VERSION 5.8 ;
BUSBITCHARS "[]" ;
DIVIDERCHAR "/" ;
UNITS
    DATABASE MICRONS 1000 ;
END UNITS

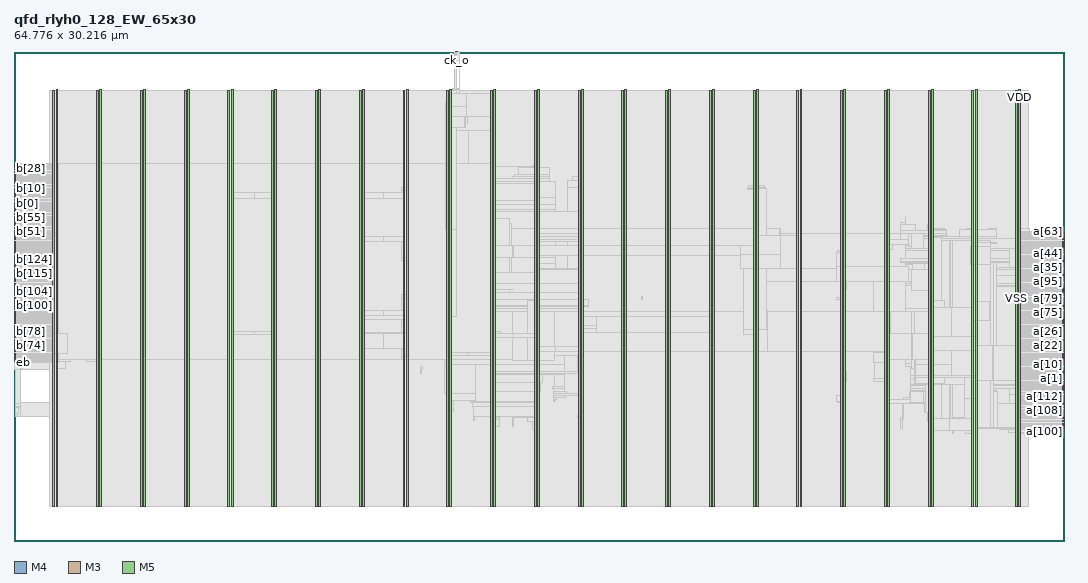
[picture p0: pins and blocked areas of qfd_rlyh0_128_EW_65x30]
MACRO qfd_rlyh0_128_EW_65x30
  FOREIGN qfd_rlyh0_128_EW_65x30 0 0 ;
  CLASS BLOCK ;
  SIZE 64.776 BY 30.216 ;
  PIN a[0]
    DIRECTION INPUT ;
    USE SIGNAL ;
    PORT
      LAYER M4 ;
        RECT  64.692 9.936 64.776 9.96 ;
    END
  END a[0]
  PIN a[100]
    DIRECTION INPUT ;
    USE SIGNAL ;
    PORT
      LAYER M4 ;
        RECT  64.692 7.248 64.776 7.272 ;
    END
  END a[100]
  PIN a[101]
    DIRECTION INPUT ;
    USE SIGNAL ;
    PORT
      LAYER M4 ;
        RECT  64.692 7.344 64.776 7.368 ;
    END
  END a[101]
  PIN a[102]
    DIRECTION INPUT ;
    USE SIGNAL ;
    PORT
      LAYER M4 ;
        RECT  64.692 7.44 64.776 7.464 ;
    END
  END a[102]
  PIN a[103]
    DIRECTION INPUT ;
    USE SIGNAL ;
    PORT
      LAYER M4 ;
        RECT  64.692 7.536 64.776 7.56 ;
    END
  END a[103]
  PIN a[104]
    DIRECTION INPUT ;
    USE SIGNAL ;
    PORT
      LAYER M4 ;
        RECT  64.692 7.632 64.776 7.656 ;
    END
  END a[104]
  PIN a[105]
    DIRECTION INPUT ;
    USE SIGNAL ;
    PORT
      LAYER M4 ;
        RECT  64.692 7.728 64.776 7.752 ;
    END
  END a[105]
  PIN a[106]
    DIRECTION INPUT ;
    USE SIGNAL ;
    PORT
      LAYER M4 ;
        RECT  64.692 7.824 64.776 7.848 ;
    END
  END a[106]
  PIN a[107]
    DIRECTION INPUT ;
    USE SIGNAL ;
    PORT
      LAYER M4 ;
        RECT  64.692 7.92 64.776 7.944 ;
    END
  END a[107]
  PIN a[108]
    DIRECTION INPUT ;
    USE SIGNAL ;
    PORT
      LAYER M4 ;
        RECT  64.692 8.016 64.776 8.04 ;
    END
  END a[108]
  PIN a[109]
    DIRECTION INPUT ;
    USE SIGNAL ;
    PORT
      LAYER M4 ;
        RECT  64.692 8.112 64.776 8.136 ;
    END
  END a[109]
  PIN a[10]
    DIRECTION INPUT ;
    USE SIGNAL ;
    PORT
      LAYER M4 ;
        RECT  64.692 10.896 64.776 10.92 ;
    END
  END a[10]
  PIN a[110]
    DIRECTION INPUT ;
    USE SIGNAL ;
    PORT
      LAYER M4 ;
        RECT  64.692 8.208 64.776 8.232 ;
    END
  END a[110]
  PIN a[111]
    DIRECTION INPUT ;
    USE SIGNAL ;
    PORT
      LAYER M4 ;
        RECT  64.692 8.304 64.776 8.328 ;
    END
  END a[111]
  PIN a[112]
    DIRECTION INPUT ;
    USE SIGNAL ;
    PORT
      LAYER M4 ;
        RECT  64.692 8.4 64.776 8.424 ;
    END
  END a[112]
  PIN a[113]
    DIRECTION INPUT ;
    USE SIGNAL ;
    PORT
      LAYER M4 ;
        RECT  64.692 8.496 64.776 8.52 ;
    END
  END a[113]
  PIN a[114]
    DIRECTION INPUT ;
    USE SIGNAL ;
    PORT
      LAYER M4 ;
        RECT  64.692 8.592 64.776 8.616 ;
    END
  END a[114]
  PIN a[115]
    DIRECTION INPUT ;
    USE SIGNAL ;
    PORT
      LAYER M4 ;
        RECT  64.692 8.688 64.776 8.712 ;
    END
  END a[115]
  PIN a[116]
    DIRECTION INPUT ;
    USE SIGNAL ;
    PORT
      LAYER M4 ;
        RECT  64.692 8.784 64.776 8.808 ;
    END
  END a[116]
  PIN a[117]
    DIRECTION INPUT ;
    USE SIGNAL ;
    PORT
      LAYER M4 ;
        RECT  64.692 8.88 64.776 8.904 ;
    END
  END a[117]
  PIN a[118]
    DIRECTION INPUT ;
    USE SIGNAL ;
    PORT
      LAYER M4 ;
        RECT  64.692 8.976 64.776 9 ;
    END
  END a[118]
  PIN a[119]
    DIRECTION INPUT ;
    USE SIGNAL ;
    PORT
      LAYER M4 ;
        RECT  64.692 9.072 64.776 9.096 ;
    END
  END a[119]
  PIN a[11]
    DIRECTION INPUT ;
    USE SIGNAL ;
    PORT
      LAYER M4 ;
        RECT  64.692 10.992 64.776 11.016 ;
    END
  END a[11]
  PIN a[120]
    DIRECTION INPUT ;
    USE SIGNAL ;
    PORT
      LAYER M4 ;
        RECT  64.692 9.168 64.776 9.192 ;
    END
  END a[120]
  PIN a[121]
    DIRECTION INPUT ;
    USE SIGNAL ;
    PORT
      LAYER M4 ;
        RECT  64.692 9.264 64.776 9.288 ;
    END
  END a[121]
  PIN a[122]
    DIRECTION INPUT ;
    USE SIGNAL ;
    PORT
      LAYER M4 ;
        RECT  64.692 9.36 64.776 9.384 ;
    END
  END a[122]
  PIN a[123]
    DIRECTION INPUT ;
    USE SIGNAL ;
    PORT
      LAYER M4 ;
        RECT  64.692 9.456 64.776 9.48 ;
    END
  END a[123]
  PIN a[124]
    DIRECTION INPUT ;
    USE SIGNAL ;
    PORT
      LAYER M4 ;
        RECT  64.692 9.552 64.776 9.576 ;
    END
  END a[124]
  PIN a[125]
    DIRECTION INPUT ;
    USE SIGNAL ;
    PORT
      LAYER M4 ;
        RECT  64.692 9.648 64.776 9.672 ;
    END
  END a[125]
  PIN a[126]
    DIRECTION INPUT ;
    USE SIGNAL ;
    PORT
      LAYER M4 ;
        RECT  64.692 9.744 64.776 9.768 ;
    END
  END a[126]
  PIN a[127]
    DIRECTION INPUT ;
    USE SIGNAL ;
    PORT
      LAYER M4 ;
        RECT  64.692 9.84 64.776 9.864 ;
    END
  END a[127]
  PIN a[12]
    DIRECTION INPUT ;
    USE SIGNAL ;
    PORT
      LAYER M4 ;
        RECT  64.692 11.088 64.776 11.112 ;
    END
  END a[12]
  PIN a[13]
    DIRECTION INPUT ;
    USE SIGNAL ;
    PORT
      LAYER M4 ;
        RECT  64.692 11.184 64.776 11.208 ;
    END
  END a[13]
  PIN a[14]
    DIRECTION INPUT ;
    USE SIGNAL ;
    PORT
      LAYER M4 ;
        RECT  64.692 11.28 64.776 11.304 ;
    END
  END a[14]
  PIN a[15]
    DIRECTION INPUT ;
    USE SIGNAL ;
    PORT
      LAYER M4 ;
        RECT  64.692 11.376 64.776 11.4 ;
    END
  END a[15]
  PIN a[16]
    DIRECTION INPUT ;
    USE SIGNAL ;
    PORT
      LAYER M4 ;
        RECT  64.692 11.472 64.776 11.496 ;
    END
  END a[16]
  PIN a[17]
    DIRECTION INPUT ;
    USE SIGNAL ;
    PORT
      LAYER M4 ;
        RECT  64.692 11.568 64.776 11.592 ;
    END
  END a[17]
  PIN a[18]
    DIRECTION INPUT ;
    USE SIGNAL ;
    PORT
      LAYER M4 ;
        RECT  64.692 11.664 64.776 11.688 ;
    END
  END a[18]
  PIN a[19]
    DIRECTION INPUT ;
    USE SIGNAL ;
    PORT
      LAYER M4 ;
        RECT  64.692 11.76 64.776 11.784 ;
    END
  END a[19]
  PIN a[1]
    DIRECTION INPUT ;
    USE SIGNAL ;
    PORT
      LAYER M4 ;
        RECT  64.692 10.032 64.776 10.056 ;
    END
  END a[1]
  PIN a[20]
    DIRECTION INPUT ;
    USE SIGNAL ;
    PORT
      LAYER M4 ;
        RECT  64.692 11.856 64.776 11.88 ;
    END
  END a[20]
  PIN a[21]
    DIRECTION INPUT ;
    USE SIGNAL ;
    PORT
      LAYER M4 ;
        RECT  64.692 11.952 64.776 11.976 ;
    END
  END a[21]
  PIN a[22]
    DIRECTION INPUT ;
    USE SIGNAL ;
    PORT
      LAYER M4 ;
        RECT  64.692 12.048 64.776 12.072 ;
    END
  END a[22]
  PIN a[23]
    DIRECTION INPUT ;
    USE SIGNAL ;
    PORT
      LAYER M4 ;
        RECT  64.692 12.144 64.776 12.168 ;
    END
  END a[23]
  PIN a[24]
    DIRECTION INPUT ;
    USE SIGNAL ;
    PORT
      LAYER M4 ;
        RECT  64.692 12.24 64.776 12.264 ;
    END
  END a[24]
  PIN a[25]
    DIRECTION INPUT ;
    USE SIGNAL ;
    PORT
      LAYER M4 ;
        RECT  64.692 12.336 64.776 12.36 ;
    END
  END a[25]
  PIN a[26]
    DIRECTION INPUT ;
    USE SIGNAL ;
    PORT
      LAYER M4 ;
        RECT  64.692 12.432 64.776 12.456 ;
    END
  END a[26]
  PIN a[27]
    DIRECTION INPUT ;
    USE SIGNAL ;
    PORT
      LAYER M4 ;
        RECT  64.692 12.528 64.776 12.552 ;
    END
  END a[27]
  PIN a[28]
    DIRECTION INPUT ;
    USE SIGNAL ;
    PORT
      LAYER M4 ;
        RECT  64.692 12.624 64.776 12.648 ;
    END
  END a[28]
  PIN a[29]
    DIRECTION INPUT ;
    USE SIGNAL ;
    PORT
      LAYER M4 ;
        RECT  64.692 12.72 64.776 12.744 ;
    END
  END a[29]
  PIN a[2]
    DIRECTION INPUT ;
    USE SIGNAL ;
    PORT
      LAYER M4 ;
        RECT  64.692 10.128 64.776 10.152 ;
    END
  END a[2]
  PIN a[30]
    DIRECTION INPUT ;
    USE SIGNAL ;
    PORT
      LAYER M4 ;
        RECT  64.692 12.816 64.776 12.84 ;
    END
  END a[30]
  PIN a[31]
    DIRECTION INPUT ;
    USE SIGNAL ;
    PORT
      LAYER M4 ;
        RECT  64.692 12.912 64.776 12.936 ;
    END
  END a[31]
  PIN a[32]
    DIRECTION INPUT ;
    USE SIGNAL ;
    PORT
      LAYER M4 ;
        RECT  64.692 16.08 64.776 16.104 ;
    END
  END a[32]
  PIN a[33]
    DIRECTION INPUT ;
    USE SIGNAL ;
    PORT
      LAYER M4 ;
        RECT  64.692 16.176 64.776 16.2 ;
    END
  END a[33]
  PIN a[34]
    DIRECTION INPUT ;
    USE SIGNAL ;
    PORT
      LAYER M4 ;
        RECT  64.692 16.272 64.776 16.296 ;
    END
  END a[34]
  PIN a[35]
    DIRECTION INPUT ;
    USE SIGNAL ;
    PORT
      LAYER M4 ;
        RECT  64.692 16.368 64.776 16.392 ;
    END
  END a[35]
  PIN a[36]
    DIRECTION INPUT ;
    USE SIGNAL ;
    PORT
      LAYER M4 ;
        RECT  64.692 16.464 64.776 16.488 ;
    END
  END a[36]
  PIN a[37]
    DIRECTION INPUT ;
    USE SIGNAL ;
    PORT
      LAYER M4 ;
        RECT  64.692 16.56 64.776 16.584 ;
    END
  END a[37]
  PIN a[38]
    DIRECTION INPUT ;
    USE SIGNAL ;
    PORT
      LAYER M4 ;
        RECT  64.692 16.656 64.776 16.68 ;
    END
  END a[38]
  PIN a[39]
    DIRECTION INPUT ;
    USE SIGNAL ;
    PORT
      LAYER M4 ;
        RECT  64.692 16.752 64.776 16.776 ;
    END
  END a[39]
  PIN a[3]
    DIRECTION INPUT ;
    USE SIGNAL ;
    PORT
      LAYER M4 ;
        RECT  64.692 10.224 64.776 10.248 ;
    END
  END a[3]
  PIN a[40]
    DIRECTION INPUT ;
    USE SIGNAL ;
    PORT
      LAYER M4 ;
        RECT  64.692 16.848 64.776 16.872 ;
    END
  END a[40]
  PIN a[41]
    DIRECTION INPUT ;
    USE SIGNAL ;
    PORT
      LAYER M4 ;
        RECT  64.692 16.944 64.776 16.968 ;
    END
  END a[41]
  PIN a[42]
    DIRECTION INPUT ;
    USE SIGNAL ;
    PORT
      LAYER M4 ;
        RECT  64.692 17.04 64.776 17.064 ;
    END
  END a[42]
  PIN a[43]
    DIRECTION INPUT ;
    USE SIGNAL ;
    PORT
      LAYER M4 ;
        RECT  64.692 17.136 64.776 17.16 ;
    END
  END a[43]
  PIN a[44]
    DIRECTION INPUT ;
    USE SIGNAL ;
    PORT
      LAYER M4 ;
        RECT  64.692 17.232 64.776 17.256 ;
    END
  END a[44]
  PIN a[45]
    DIRECTION INPUT ;
    USE SIGNAL ;
    PORT
      LAYER M4 ;
        RECT  64.692 17.328 64.776 17.352 ;
    END
  END a[45]
  PIN a[46]
    DIRECTION INPUT ;
    USE SIGNAL ;
    PORT
      LAYER M4 ;
        RECT  64.692 17.424 64.776 17.448 ;
    END
  END a[46]
  PIN a[47]
    DIRECTION INPUT ;
    USE SIGNAL ;
    PORT
      LAYER M4 ;
        RECT  64.692 17.52 64.776 17.544 ;
    END
  END a[47]
  PIN a[48]
    DIRECTION INPUT ;
    USE SIGNAL ;
    PORT
      LAYER M4 ;
        RECT  64.692 17.616 64.776 17.64 ;
    END
  END a[48]
  PIN a[49]
    DIRECTION INPUT ;
    USE SIGNAL ;
    PORT
      LAYER M4 ;
        RECT  64.692 17.712 64.776 17.736 ;
    END
  END a[49]
  PIN a[4]
    DIRECTION INPUT ;
    USE SIGNAL ;
    PORT
      LAYER M4 ;
        RECT  64.692 10.32 64.776 10.344 ;
    END
  END a[4]
  PIN a[50]
    DIRECTION INPUT ;
    USE SIGNAL ;
    PORT
      LAYER M4 ;
        RECT  64.692 17.808 64.776 17.832 ;
    END
  END a[50]
  PIN a[51]
    DIRECTION INPUT ;
    USE SIGNAL ;
    PORT
      LAYER M4 ;
        RECT  64.692 17.904 64.776 17.928 ;
    END
  END a[51]
  PIN a[52]
    DIRECTION INPUT ;
    USE SIGNAL ;
    PORT
      LAYER M4 ;
        RECT  64.692 18 64.776 18.024 ;
    END
  END a[52]
  PIN a[53]
    DIRECTION INPUT ;
    USE SIGNAL ;
    PORT
      LAYER M4 ;
        RECT  64.692 18.096 64.776 18.12 ;
    END
  END a[53]
  PIN a[54]
    DIRECTION INPUT ;
    USE SIGNAL ;
    PORT
      LAYER M4 ;
        RECT  64.692 18.192 64.776 18.216 ;
    END
  END a[54]
  PIN a[55]
    DIRECTION INPUT ;
    USE SIGNAL ;
    PORT
      LAYER M4 ;
        RECT  64.692 18.288 64.776 18.312 ;
    END
  END a[55]
  PIN a[56]
    DIRECTION INPUT ;
    USE SIGNAL ;
    PORT
      LAYER M4 ;
        RECT  64.692 18.384 64.776 18.408 ;
    END
  END a[56]
  PIN a[57]
    DIRECTION INPUT ;
    USE SIGNAL ;
    PORT
      LAYER M4 ;
        RECT  64.692 18.48 64.776 18.504 ;
    END
  END a[57]
  PIN a[58]
    DIRECTION INPUT ;
    USE SIGNAL ;
    PORT
      LAYER M4 ;
        RECT  64.692 18.576 64.776 18.6 ;
    END
  END a[58]
  PIN a[59]
    DIRECTION INPUT ;
    USE SIGNAL ;
    PORT
      LAYER M4 ;
        RECT  64.692 18.672 64.776 18.696 ;
    END
  END a[59]
  PIN a[5]
    DIRECTION INPUT ;
    USE SIGNAL ;
    PORT
      LAYER M4 ;
        RECT  64.692 10.416 64.776 10.44 ;
    END
  END a[5]
  PIN a[60]
    DIRECTION INPUT ;
    USE SIGNAL ;
    PORT
      LAYER M4 ;
        RECT  64.692 18.768 64.776 18.792 ;
    END
  END a[60]
  PIN a[61]
    DIRECTION INPUT ;
    USE SIGNAL ;
    PORT
      LAYER M4 ;
        RECT  64.692 18.864 64.776 18.888 ;
    END
  END a[61]
  PIN a[62]
    DIRECTION INPUT ;
    USE SIGNAL ;
    PORT
      LAYER M4 ;
        RECT  64.692 18.96 64.776 18.984 ;
    END
  END a[62]
  PIN a[63]
    DIRECTION INPUT ;
    USE SIGNAL ;
    PORT
      LAYER M4 ;
        RECT  64.692 19.056 64.776 19.08 ;
    END
  END a[63]
  PIN a[64]
    DIRECTION INPUT ;
    USE SIGNAL ;
    PORT
      LAYER M4 ;
        RECT  64.692 13.008 64.776 13.032 ;
    END
  END a[64]
  PIN a[65]
    DIRECTION INPUT ;
    USE SIGNAL ;
    PORT
      LAYER M4 ;
        RECT  64.692 13.104 64.776 13.128 ;
    END
  END a[65]
  PIN a[66]
    DIRECTION INPUT ;
    USE SIGNAL ;
    PORT
      LAYER M4 ;
        RECT  64.692 13.2 64.776 13.224 ;
    END
  END a[66]
  PIN a[67]
    DIRECTION INPUT ;
    USE SIGNAL ;
    PORT
      LAYER M4 ;
        RECT  64.692 13.296 64.776 13.32 ;
    END
  END a[67]
  PIN a[68]
    DIRECTION INPUT ;
    USE SIGNAL ;
    PORT
      LAYER M4 ;
        RECT  64.692 13.392 64.776 13.416 ;
    END
  END a[68]
  PIN a[69]
    DIRECTION INPUT ;
    USE SIGNAL ;
    PORT
      LAYER M4 ;
        RECT  64.692 13.488 64.776 13.512 ;
    END
  END a[69]
  PIN a[6]
    DIRECTION INPUT ;
    USE SIGNAL ;
    PORT
      LAYER M4 ;
        RECT  64.692 10.512 64.776 10.536 ;
    END
  END a[6]
  PIN a[70]
    DIRECTION INPUT ;
    USE SIGNAL ;
    PORT
      LAYER M4 ;
        RECT  64.692 13.584 64.776 13.608 ;
    END
  END a[70]
  PIN a[71]
    DIRECTION INPUT ;
    USE SIGNAL ;
    PORT
      LAYER M4 ;
        RECT  64.692 13.68 64.776 13.704 ;
    END
  END a[71]
  PIN a[72]
    DIRECTION INPUT ;
    USE SIGNAL ;
    PORT
      LAYER M4 ;
        RECT  64.692 13.776 64.776 13.8 ;
    END
  END a[72]
  PIN a[73]
    DIRECTION INPUT ;
    USE SIGNAL ;
    PORT
      LAYER M4 ;
        RECT  64.692 13.872 64.776 13.896 ;
    END
  END a[73]
  PIN a[74]
    DIRECTION INPUT ;
    USE SIGNAL ;
    PORT
      LAYER M4 ;
        RECT  64.692 13.968 64.776 13.992 ;
    END
  END a[74]
  PIN a[75]
    DIRECTION INPUT ;
    USE SIGNAL ;
    PORT
      LAYER M4 ;
        RECT  64.692 14.064 64.776 14.088 ;
    END
  END a[75]
  PIN a[76]
    DIRECTION INPUT ;
    USE SIGNAL ;
    PORT
      LAYER M4 ;
        RECT  64.692 14.16 64.776 14.184 ;
    END
  END a[76]
  PIN a[77]
    DIRECTION INPUT ;
    USE SIGNAL ;
    PORT
      LAYER M4 ;
        RECT  64.692 14.256 64.776 14.28 ;
    END
  END a[77]
  PIN a[78]
    DIRECTION INPUT ;
    USE SIGNAL ;
    PORT
      LAYER M4 ;
        RECT  64.692 14.352 64.776 14.376 ;
    END
  END a[78]
  PIN a[79]
    DIRECTION INPUT ;
    USE SIGNAL ;
    PORT
      LAYER M4 ;
        RECT  64.692 14.448 64.776 14.472 ;
    END
  END a[79]
  PIN a[7]
    DIRECTION INPUT ;
    USE SIGNAL ;
    PORT
      LAYER M4 ;
        RECT  64.692 10.608 64.776 10.632 ;
    END
  END a[7]
  PIN a[80]
    DIRECTION INPUT ;
    USE SIGNAL ;
    PORT
      LAYER M4 ;
        RECT  64.692 14.544 64.776 14.568 ;
    END
  END a[80]
  PIN a[81]
    DIRECTION INPUT ;
    USE SIGNAL ;
    PORT
      LAYER M4 ;
        RECT  64.692 14.64 64.776 14.664 ;
    END
  END a[81]
  PIN a[82]
    DIRECTION INPUT ;
    USE SIGNAL ;
    PORT
      LAYER M4 ;
        RECT  64.692 14.736 64.776 14.76 ;
    END
  END a[82]
  PIN a[83]
    DIRECTION INPUT ;
    USE SIGNAL ;
    PORT
      LAYER M4 ;
        RECT  64.692 14.832 64.776 14.856 ;
    END
  END a[83]
  PIN a[84]
    DIRECTION INPUT ;
    USE SIGNAL ;
    PORT
      LAYER M4 ;
        RECT  64.692 14.928 64.776 14.952 ;
    END
  END a[84]
  PIN a[85]
    DIRECTION INPUT ;
    USE SIGNAL ;
    PORT
      LAYER M4 ;
        RECT  64.692 15.024 64.776 15.048 ;
    END
  END a[85]
  PIN a[86]
    DIRECTION INPUT ;
    USE SIGNAL ;
    PORT
      LAYER M4 ;
        RECT  64.692 15.12 64.776 15.144 ;
    END
  END a[86]
  PIN a[87]
    DIRECTION INPUT ;
    USE SIGNAL ;
    PORT
      LAYER M4 ;
        RECT  64.692 15.216 64.776 15.24 ;
    END
  END a[87]
  PIN a[88]
    DIRECTION INPUT ;
    USE SIGNAL ;
    PORT
      LAYER M4 ;
        RECT  64.692 15.312 64.776 15.336 ;
    END
  END a[88]
  PIN a[89]
    DIRECTION INPUT ;
    USE SIGNAL ;
    PORT
      LAYER M4 ;
        RECT  64.692 15.408 64.776 15.432 ;
    END
  END a[89]
  PIN a[8]
    DIRECTION INPUT ;
    USE SIGNAL ;
    PORT
      LAYER M4 ;
        RECT  64.692 10.704 64.776 10.728 ;
    END
  END a[8]
  PIN a[90]
    DIRECTION INPUT ;
    USE SIGNAL ;
    PORT
      LAYER M4 ;
        RECT  64.692 15.504 64.776 15.528 ;
    END
  END a[90]
  PIN a[91]
    DIRECTION INPUT ;
    USE SIGNAL ;
    PORT
      LAYER M4 ;
        RECT  64.692 15.6 64.776 15.624 ;
    END
  END a[91]
  PIN a[92]
    DIRECTION INPUT ;
    USE SIGNAL ;
    PORT
      LAYER M4 ;
        RECT  64.692 15.696 64.776 15.72 ;
    END
  END a[92]
  PIN a[93]
    DIRECTION INPUT ;
    USE SIGNAL ;
    PORT
      LAYER M4 ;
        RECT  64.692 15.792 64.776 15.816 ;
    END
  END a[93]
  PIN a[94]
    DIRECTION INPUT ;
    USE SIGNAL ;
    PORT
      LAYER M4 ;
        RECT  64.692 15.888 64.776 15.912 ;
    END
  END a[94]
  PIN a[95]
    DIRECTION INPUT ;
    USE SIGNAL ;
    PORT
      LAYER M4 ;
        RECT  64.692 15.984 64.776 16.008 ;
    END
  END a[95]
  PIN a[96]
    DIRECTION INPUT ;
    USE SIGNAL ;
    PORT
      LAYER M4 ;
        RECT  64.692 6.864 64.776 6.888 ;
    END
  END a[96]
  PIN a[97]
    DIRECTION INPUT ;
    USE SIGNAL ;
    PORT
      LAYER M4 ;
        RECT  64.692 6.96 64.776 6.984 ;
    END
  END a[97]
  PIN a[98]
    DIRECTION INPUT ;
    USE SIGNAL ;
    PORT
      LAYER M4 ;
        RECT  64.692 7.056 64.776 7.08 ;
    END
  END a[98]
  PIN a[99]
    DIRECTION INPUT ;
    USE SIGNAL ;
    PORT
      LAYER M4 ;
        RECT  64.692 7.152 64.776 7.176 ;
    END
  END a[99]
  PIN a[9]
    DIRECTION INPUT ;
    USE SIGNAL ;
    PORT
      LAYER M4 ;
        RECT  64.692 10.8 64.776 10.824 ;
    END
  END a[9]
  PIN b[0]
    DIRECTION OUTPUT ;
    USE SIGNAL ;
    PORT
      LAYER M4 ;
        RECT  0 20.304 0.084 20.328 ;
    END
  END b[0]
  PIN b[100]
    DIRECTION OUTPUT ;
    USE SIGNAL ;
    PORT
      LAYER M4 ;
        RECT  0 14.544 0.084 14.568 ;
    END
  END b[100]
  PIN b[101]
    DIRECTION OUTPUT ;
    USE SIGNAL ;
    PORT
      LAYER M4 ;
        RECT  0 14.64 0.084 14.664 ;
    END
  END b[101]
  PIN b[102]
    DIRECTION OUTPUT ;
    USE SIGNAL ;
    PORT
      LAYER M4 ;
        RECT  0 14.736 0.084 14.76 ;
    END
  END b[102]
  PIN b[103]
    DIRECTION OUTPUT ;
    USE SIGNAL ;
    PORT
      LAYER M4 ;
        RECT  0 14.832 0.084 14.856 ;
    END
  END b[103]
  PIN b[104]
    DIRECTION OUTPUT ;
    USE SIGNAL ;
    PORT
      LAYER M4 ;
        RECT  0 14.928 0.084 14.952 ;
    END
  END b[104]
  PIN b[105]
    DIRECTION OUTPUT ;
    USE SIGNAL ;
    PORT
      LAYER M4 ;
        RECT  0 15.024 0.084 15.048 ;
    END
  END b[105]
  PIN b[106]
    DIRECTION OUTPUT ;
    USE SIGNAL ;
    PORT
      LAYER M4 ;
        RECT  0 15.12 0.084 15.144 ;
    END
  END b[106]
  PIN b[107]
    DIRECTION OUTPUT ;
    USE SIGNAL ;
    PORT
      LAYER M4 ;
        RECT  0 15.216 0.084 15.24 ;
    END
  END b[107]
  PIN b[108]
    DIRECTION OUTPUT ;
    USE SIGNAL ;
    PORT
      LAYER M4 ;
        RECT  0 15.312 0.084 15.336 ;
    END
  END b[108]
  PIN b[109]
    DIRECTION OUTPUT ;
    USE SIGNAL ;
    PORT
      LAYER M4 ;
        RECT  0 15.408 0.084 15.432 ;
    END
  END b[109]
  PIN b[10]
    DIRECTION OUTPUT ;
    USE SIGNAL ;
    PORT
      LAYER M4 ;
        RECT  0 21.264 0.084 21.288 ;
    END
  END b[10]
  PIN b[110]
    DIRECTION OUTPUT ;
    USE SIGNAL ;
    PORT
      LAYER M4 ;
        RECT  0 15.504 0.084 15.528 ;
    END
  END b[110]
  PIN b[111]
    DIRECTION OUTPUT ;
    USE SIGNAL ;
    PORT
      LAYER M4 ;
        RECT  0 15.6 0.084 15.624 ;
    END
  END b[111]
  PIN b[112]
    DIRECTION OUTPUT ;
    USE SIGNAL ;
    PORT
      LAYER M4 ;
        RECT  0 15.696 0.084 15.72 ;
    END
  END b[112]
  PIN b[113]
    DIRECTION OUTPUT ;
    USE SIGNAL ;
    PORT
      LAYER M4 ;
        RECT  0 15.792 0.084 15.816 ;
    END
  END b[113]
  PIN b[114]
    DIRECTION OUTPUT ;
    USE SIGNAL ;
    PORT
      LAYER M4 ;
        RECT  0 15.888 0.084 15.912 ;
    END
  END b[114]
  PIN b[115]
    DIRECTION OUTPUT ;
    USE SIGNAL ;
    PORT
      LAYER M4 ;
        RECT  0 15.984 0.084 16.008 ;
    END
  END b[115]
  PIN b[116]
    DIRECTION OUTPUT ;
    USE SIGNAL ;
    PORT
      LAYER M4 ;
        RECT  0 16.08 0.084 16.104 ;
    END
  END b[116]
  PIN b[117]
    DIRECTION OUTPUT ;
    USE SIGNAL ;
    PORT
      LAYER M4 ;
        RECT  0 16.176 0.084 16.2 ;
    END
  END b[117]
  PIN b[118]
    DIRECTION OUTPUT ;
    USE SIGNAL ;
    PORT
      LAYER M4 ;
        RECT  0 16.272 0.084 16.296 ;
    END
  END b[118]
  PIN b[119]
    DIRECTION OUTPUT ;
    USE SIGNAL ;
    PORT
      LAYER M4 ;
        RECT  0 16.368 0.084 16.392 ;
    END
  END b[119]
  PIN b[11]
    DIRECTION OUTPUT ;
    USE SIGNAL ;
    PORT
      LAYER M4 ;
        RECT  0 21.36 0.084 21.384 ;
    END
  END b[11]
  PIN b[120]
    DIRECTION OUTPUT ;
    USE SIGNAL ;
    PORT
      LAYER M4 ;
        RECT  0 16.464 0.084 16.488 ;
    END
  END b[120]
  PIN b[121]
    DIRECTION OUTPUT ;
    USE SIGNAL ;
    PORT
      LAYER M4 ;
        RECT  0 16.56 0.084 16.584 ;
    END
  END b[121]
  PIN b[122]
    DIRECTION OUTPUT ;
    USE SIGNAL ;
    PORT
      LAYER M4 ;
        RECT  0 16.656 0.084 16.68 ;
    END
  END b[122]
  PIN b[123]
    DIRECTION OUTPUT ;
    USE SIGNAL ;
    PORT
      LAYER M4 ;
        RECT  0 16.752 0.084 16.776 ;
    END
  END b[123]
  PIN b[124]
    DIRECTION OUTPUT ;
    USE SIGNAL ;
    PORT
      LAYER M4 ;
        RECT  0 16.848 0.084 16.872 ;
    END
  END b[124]
  PIN b[125]
    DIRECTION OUTPUT ;
    USE SIGNAL ;
    PORT
      LAYER M4 ;
        RECT  0 16.944 0.084 16.968 ;
    END
  END b[125]
  PIN b[126]
    DIRECTION OUTPUT ;
    USE SIGNAL ;
    PORT
      LAYER M4 ;
        RECT  0 17.04 0.084 17.064 ;
    END
  END b[126]
  PIN b[127]
    DIRECTION OUTPUT ;
    USE SIGNAL ;
    PORT
      LAYER M4 ;
        RECT  0 17.136 0.084 17.16 ;
    END
  END b[127]
  PIN b[12]
    DIRECTION OUTPUT ;
    USE SIGNAL ;
    PORT
      LAYER M4 ;
        RECT  0 21.456 0.084 21.48 ;
    END
  END b[12]
  PIN b[13]
    DIRECTION OUTPUT ;
    USE SIGNAL ;
    PORT
      LAYER M4 ;
        RECT  0 21.552 0.084 21.576 ;
    END
  END b[13]
  PIN b[14]
    DIRECTION OUTPUT ;
    USE SIGNAL ;
    PORT
      LAYER M4 ;
        RECT  0 21.648 0.084 21.672 ;
    END
  END b[14]
  PIN b[15]
    DIRECTION OUTPUT ;
    USE SIGNAL ;
    PORT
      LAYER M4 ;
        RECT  0 21.744 0.084 21.768 ;
    END
  END b[15]
  PIN b[16]
    DIRECTION OUTPUT ;
    USE SIGNAL ;
    PORT
      LAYER M4 ;
        RECT  0 21.84 0.084 21.864 ;
    END
  END b[16]
  PIN b[17]
    DIRECTION OUTPUT ;
    USE SIGNAL ;
    PORT
      LAYER M4 ;
        RECT  0 21.936 0.084 21.96 ;
    END
  END b[17]
  PIN b[18]
    DIRECTION OUTPUT ;
    USE SIGNAL ;
    PORT
      LAYER M4 ;
        RECT  0 22.032 0.084 22.056 ;
    END
  END b[18]
  PIN b[19]
    DIRECTION OUTPUT ;
    USE SIGNAL ;
    PORT
      LAYER M4 ;
        RECT  0 22.128 0.084 22.152 ;
    END
  END b[19]
  PIN b[1]
    DIRECTION OUTPUT ;
    USE SIGNAL ;
    PORT
      LAYER M4 ;
        RECT  0 20.4 0.084 20.424 ;
    END
  END b[1]
  PIN b[20]
    DIRECTION OUTPUT ;
    USE SIGNAL ;
    PORT
      LAYER M4 ;
        RECT  0 22.224 0.084 22.248 ;
    END
  END b[20]
  PIN b[21]
    DIRECTION OUTPUT ;
    USE SIGNAL ;
    PORT
      LAYER M4 ;
        RECT  0 22.32 0.084 22.344 ;
    END
  END b[21]
  PIN b[22]
    DIRECTION OUTPUT ;
    USE SIGNAL ;
    PORT
      LAYER M4 ;
        RECT  0 22.416 0.084 22.44 ;
    END
  END b[22]
  PIN b[23]
    DIRECTION OUTPUT ;
    USE SIGNAL ;
    PORT
      LAYER M4 ;
        RECT  0 22.512 0.084 22.536 ;
    END
  END b[23]
  PIN b[24]
    DIRECTION OUTPUT ;
    USE SIGNAL ;
    PORT
      LAYER M4 ;
        RECT  0 22.608 0.084 22.632 ;
    END
  END b[24]
  PIN b[25]
    DIRECTION OUTPUT ;
    USE SIGNAL ;
    PORT
      LAYER M4 ;
        RECT  0 22.704 0.084 22.728 ;
    END
  END b[25]
  PIN b[26]
    DIRECTION OUTPUT ;
    USE SIGNAL ;
    PORT
      LAYER M4 ;
        RECT  0 22.8 0.084 22.824 ;
    END
  END b[26]
  PIN b[27]
    DIRECTION OUTPUT ;
    USE SIGNAL ;
    PORT
      LAYER M4 ;
        RECT  0 22.896 0.084 22.92 ;
    END
  END b[27]
  PIN b[28]
    DIRECTION OUTPUT ;
    USE SIGNAL ;
    PORT
      LAYER M4 ;
        RECT  0 22.992 0.084 23.016 ;
    END
  END b[28]
  PIN b[29]
    DIRECTION OUTPUT ;
    USE SIGNAL ;
    PORT
      LAYER M4 ;
        RECT  0 23.088 0.084 23.112 ;
    END
  END b[29]
  PIN b[2]
    DIRECTION OUTPUT ;
    USE SIGNAL ;
    PORT
      LAYER M4 ;
        RECT  0 20.496 0.084 20.52 ;
    END
  END b[2]
  PIN b[30]
    DIRECTION OUTPUT ;
    USE SIGNAL ;
    PORT
      LAYER M4 ;
        RECT  0 23.184 0.084 23.208 ;
    END
  END b[30]
  PIN b[31]
    DIRECTION OUTPUT ;
    USE SIGNAL ;
    PORT
      LAYER M4 ;
        RECT  0 23.28 0.084 23.304 ;
    END
  END b[31]
  PIN b[32]
    DIRECTION OUTPUT ;
    USE SIGNAL ;
    PORT
      LAYER M4 ;
        RECT  0 17.232 0.084 17.256 ;
    END
  END b[32]
  PIN b[33]
    DIRECTION OUTPUT ;
    USE SIGNAL ;
    PORT
      LAYER M4 ;
        RECT  0 17.328 0.084 17.352 ;
    END
  END b[33]
  PIN b[34]
    DIRECTION OUTPUT ;
    USE SIGNAL ;
    PORT
      LAYER M4 ;
        RECT  0 17.424 0.084 17.448 ;
    END
  END b[34]
  PIN b[35]
    DIRECTION OUTPUT ;
    USE SIGNAL ;
    PORT
      LAYER M4 ;
        RECT  0 17.52 0.084 17.544 ;
    END
  END b[35]
  PIN b[36]
    DIRECTION OUTPUT ;
    USE SIGNAL ;
    PORT
      LAYER M4 ;
        RECT  0 17.616 0.084 17.64 ;
    END
  END b[36]
  PIN b[37]
    DIRECTION OUTPUT ;
    USE SIGNAL ;
    PORT
      LAYER M4 ;
        RECT  0 17.712 0.084 17.736 ;
    END
  END b[37]
  PIN b[38]
    DIRECTION OUTPUT ;
    USE SIGNAL ;
    PORT
      LAYER M4 ;
        RECT  0 17.808 0.084 17.832 ;
    END
  END b[38]
  PIN b[39]
    DIRECTION OUTPUT ;
    USE SIGNAL ;
    PORT
      LAYER M4 ;
        RECT  0 17.904 0.084 17.928 ;
    END
  END b[39]
  PIN b[3]
    DIRECTION OUTPUT ;
    USE SIGNAL ;
    PORT
      LAYER M4 ;
        RECT  0 20.592 0.084 20.616 ;
    END
  END b[3]
  PIN b[40]
    DIRECTION OUTPUT ;
    USE SIGNAL ;
    PORT
      LAYER M4 ;
        RECT  0 18 0.084 18.024 ;
    END
  END b[40]
  PIN b[41]
    DIRECTION OUTPUT ;
    USE SIGNAL ;
    PORT
      LAYER M4 ;
        RECT  0 18.096 0.084 18.12 ;
    END
  END b[41]
  PIN b[42]
    DIRECTION OUTPUT ;
    USE SIGNAL ;
    PORT
      LAYER M4 ;
        RECT  0 18.192 0.084 18.216 ;
    END
  END b[42]
  PIN b[43]
    DIRECTION OUTPUT ;
    USE SIGNAL ;
    PORT
      LAYER M4 ;
        RECT  0 18.288 0.084 18.312 ;
    END
  END b[43]
  PIN b[44]
    DIRECTION OUTPUT ;
    USE SIGNAL ;
    PORT
      LAYER M4 ;
        RECT  0 18.384 0.084 18.408 ;
    END
  END b[44]
  PIN b[45]
    DIRECTION OUTPUT ;
    USE SIGNAL ;
    PORT
      LAYER M4 ;
        RECT  0 18.48 0.084 18.504 ;
    END
  END b[45]
  PIN b[46]
    DIRECTION OUTPUT ;
    USE SIGNAL ;
    PORT
      LAYER M4 ;
        RECT  0 18.576 0.084 18.6 ;
    END
  END b[46]
  PIN b[47]
    DIRECTION OUTPUT ;
    USE SIGNAL ;
    PORT
      LAYER M4 ;
        RECT  0 18.672 0.084 18.696 ;
    END
  END b[47]
  PIN b[48]
    DIRECTION OUTPUT ;
    USE SIGNAL ;
    PORT
      LAYER M4 ;
        RECT  0 18.768 0.084 18.792 ;
    END
  END b[48]
  PIN b[49]
    DIRECTION OUTPUT ;
    USE SIGNAL ;
    PORT
      LAYER M4 ;
        RECT  0 18.864 0.084 18.888 ;
    END
  END b[49]
  PIN b[4]
    DIRECTION OUTPUT ;
    USE SIGNAL ;
    PORT
      LAYER M4 ;
        RECT  0 20.688 0.084 20.712 ;
    END
  END b[4]
  PIN b[50]
    DIRECTION OUTPUT ;
    USE SIGNAL ;
    PORT
      LAYER M4 ;
        RECT  0 18.96 0.084 18.984 ;
    END
  END b[50]
  PIN b[51]
    DIRECTION OUTPUT ;
    USE SIGNAL ;
    PORT
      LAYER M4 ;
        RECT  0 19.056 0.084 19.08 ;
    END
  END b[51]
  PIN b[52]
    DIRECTION OUTPUT ;
    USE SIGNAL ;
    PORT
      LAYER M4 ;
        RECT  0 19.152 0.084 19.176 ;
    END
  END b[52]
  PIN b[53]
    DIRECTION OUTPUT ;
    USE SIGNAL ;
    PORT
      LAYER M4 ;
        RECT  0 19.248 0.084 19.272 ;
    END
  END b[53]
  PIN b[54]
    DIRECTION OUTPUT ;
    USE SIGNAL ;
    PORT
      LAYER M4 ;
        RECT  0 19.344 0.084 19.368 ;
    END
  END b[54]
  PIN b[55]
    DIRECTION OUTPUT ;
    USE SIGNAL ;
    PORT
      LAYER M4 ;
        RECT  0 19.44 0.084 19.464 ;
    END
  END b[55]
  PIN b[56]
    DIRECTION OUTPUT ;
    USE SIGNAL ;
    PORT
      LAYER M4 ;
        RECT  0 19.536 0.084 19.56 ;
    END
  END b[56]
  PIN b[57]
    DIRECTION OUTPUT ;
    USE SIGNAL ;
    PORT
      LAYER M4 ;
        RECT  0 19.632 0.084 19.656 ;
    END
  END b[57]
  PIN b[58]
    DIRECTION OUTPUT ;
    USE SIGNAL ;
    PORT
      LAYER M4 ;
        RECT  0 19.728 0.084 19.752 ;
    END
  END b[58]
  PIN b[59]
    DIRECTION OUTPUT ;
    USE SIGNAL ;
    PORT
      LAYER M4 ;
        RECT  0 19.824 0.084 19.848 ;
    END
  END b[59]
  PIN b[5]
    DIRECTION OUTPUT ;
    USE SIGNAL ;
    PORT
      LAYER M4 ;
        RECT  0 20.784 0.084 20.808 ;
    END
  END b[5]
  PIN b[60]
    DIRECTION OUTPUT ;
    USE SIGNAL ;
    PORT
      LAYER M4 ;
        RECT  0 19.92 0.084 19.944 ;
    END
  END b[60]
  PIN b[61]
    DIRECTION OUTPUT ;
    USE SIGNAL ;
    PORT
      LAYER M4 ;
        RECT  0 20.016 0.084 20.04 ;
    END
  END b[61]
  PIN b[62]
    DIRECTION OUTPUT ;
    USE SIGNAL ;
    PORT
      LAYER M4 ;
        RECT  0 20.112 0.084 20.136 ;
    END
  END b[62]
  PIN b[63]
    DIRECTION OUTPUT ;
    USE SIGNAL ;
    PORT
      LAYER M4 ;
        RECT  0 20.208 0.084 20.232 ;
    END
  END b[63]
  PIN b[64]
    DIRECTION OUTPUT ;
    USE SIGNAL ;
    PORT
      LAYER M4 ;
        RECT  0 11.088 0.084 11.112 ;
    END
  END b[64]
  PIN b[65]
    DIRECTION OUTPUT ;
    USE SIGNAL ;
    PORT
      LAYER M4 ;
        RECT  0 11.184 0.084 11.208 ;
    END
  END b[65]
  PIN b[66]
    DIRECTION OUTPUT ;
    USE SIGNAL ;
    PORT
      LAYER M4 ;
        RECT  0 11.28 0.084 11.304 ;
    END
  END b[66]
  PIN b[67]
    DIRECTION OUTPUT ;
    USE SIGNAL ;
    PORT
      LAYER M4 ;
        RECT  0 11.376 0.084 11.4 ;
    END
  END b[67]
  PIN b[68]
    DIRECTION OUTPUT ;
    USE SIGNAL ;
    PORT
      LAYER M4 ;
        RECT  0 11.472 0.084 11.496 ;
    END
  END b[68]
  PIN b[69]
    DIRECTION OUTPUT ;
    USE SIGNAL ;
    PORT
      LAYER M4 ;
        RECT  0 11.568 0.084 11.592 ;
    END
  END b[69]
  PIN b[6]
    DIRECTION OUTPUT ;
    USE SIGNAL ;
    PORT
      LAYER M4 ;
        RECT  0 20.88 0.084 20.904 ;
    END
  END b[6]
  PIN b[70]
    DIRECTION OUTPUT ;
    USE SIGNAL ;
    PORT
      LAYER M4 ;
        RECT  0 11.664 0.084 11.688 ;
    END
  END b[70]
  PIN b[71]
    DIRECTION OUTPUT ;
    USE SIGNAL ;
    PORT
      LAYER M4 ;
        RECT  0 11.76 0.084 11.784 ;
    END
  END b[71]
  PIN b[72]
    DIRECTION OUTPUT ;
    USE SIGNAL ;
    PORT
      LAYER M4 ;
        RECT  0 11.856 0.084 11.88 ;
    END
  END b[72]
  PIN b[73]
    DIRECTION OUTPUT ;
    USE SIGNAL ;
    PORT
      LAYER M4 ;
        RECT  0 11.952 0.084 11.976 ;
    END
  END b[73]
  PIN b[74]
    DIRECTION OUTPUT ;
    USE SIGNAL ;
    PORT
      LAYER M4 ;
        RECT  0 12.048 0.084 12.072 ;
    END
  END b[74]
  PIN b[75]
    DIRECTION OUTPUT ;
    USE SIGNAL ;
    PORT
      LAYER M4 ;
        RECT  0 12.144 0.084 12.168 ;
    END
  END b[75]
  PIN b[76]
    DIRECTION OUTPUT ;
    USE SIGNAL ;
    PORT
      LAYER M4 ;
        RECT  0 12.24 0.084 12.264 ;
    END
  END b[76]
  PIN b[77]
    DIRECTION OUTPUT ;
    USE SIGNAL ;
    PORT
      LAYER M4 ;
        RECT  0 12.336 0.084 12.36 ;
    END
  END b[77]
  PIN b[78]
    DIRECTION OUTPUT ;
    USE SIGNAL ;
    PORT
      LAYER M4 ;
        RECT  0 12.432 0.084 12.456 ;
    END
  END b[78]
  PIN b[79]
    DIRECTION OUTPUT ;
    USE SIGNAL ;
    PORT
      LAYER M4 ;
        RECT  0 12.528 0.084 12.552 ;
    END
  END b[79]
  PIN b[7]
    DIRECTION OUTPUT ;
    USE SIGNAL ;
    PORT
      LAYER M4 ;
        RECT  0 20.976 0.084 21 ;
    END
  END b[7]
  PIN b[80]
    DIRECTION OUTPUT ;
    USE SIGNAL ;
    PORT
      LAYER M4 ;
        RECT  0 12.624 0.084 12.648 ;
    END
  END b[80]
  PIN b[81]
    DIRECTION OUTPUT ;
    USE SIGNAL ;
    PORT
      LAYER M4 ;
        RECT  0 12.72 0.084 12.744 ;
    END
  END b[81]
  PIN b[82]
    DIRECTION OUTPUT ;
    USE SIGNAL ;
    PORT
      LAYER M4 ;
        RECT  0 12.816 0.084 12.84 ;
    END
  END b[82]
  PIN b[83]
    DIRECTION OUTPUT ;
    USE SIGNAL ;
    PORT
      LAYER M4 ;
        RECT  0 12.912 0.084 12.936 ;
    END
  END b[83]
  PIN b[84]
    DIRECTION OUTPUT ;
    USE SIGNAL ;
    PORT
      LAYER M4 ;
        RECT  0 13.008 0.084 13.032 ;
    END
  END b[84]
  PIN b[85]
    DIRECTION OUTPUT ;
    USE SIGNAL ;
    PORT
      LAYER M4 ;
        RECT  0 13.104 0.084 13.128 ;
    END
  END b[85]
  PIN b[86]
    DIRECTION OUTPUT ;
    USE SIGNAL ;
    PORT
      LAYER M4 ;
        RECT  0 13.2 0.084 13.224 ;
    END
  END b[86]
  PIN b[87]
    DIRECTION OUTPUT ;
    USE SIGNAL ;
    PORT
      LAYER M4 ;
        RECT  0 13.296 0.084 13.32 ;
    END
  END b[87]
  PIN b[88]
    DIRECTION OUTPUT ;
    USE SIGNAL ;
    PORT
      LAYER M4 ;
        RECT  0 13.392 0.084 13.416 ;
    END
  END b[88]
  PIN b[89]
    DIRECTION OUTPUT ;
    USE SIGNAL ;
    PORT
      LAYER M4 ;
        RECT  0 13.488 0.084 13.512 ;
    END
  END b[89]
  PIN b[8]
    DIRECTION OUTPUT ;
    USE SIGNAL ;
    PORT
      LAYER M4 ;
        RECT  0 21.072 0.084 21.096 ;
    END
  END b[8]
  PIN b[90]
    DIRECTION OUTPUT ;
    USE SIGNAL ;
    PORT
      LAYER M4 ;
        RECT  0 13.584 0.084 13.608 ;
    END
  END b[90]
  PIN b[91]
    DIRECTION OUTPUT ;
    USE SIGNAL ;
    PORT
      LAYER M4 ;
        RECT  0 13.68 0.084 13.704 ;
    END
  END b[91]
  PIN b[92]
    DIRECTION OUTPUT ;
    USE SIGNAL ;
    PORT
      LAYER M4 ;
        RECT  0 13.776 0.084 13.8 ;
    END
  END b[92]
  PIN b[93]
    DIRECTION OUTPUT ;
    USE SIGNAL ;
    PORT
      LAYER M4 ;
        RECT  0 13.872 0.084 13.896 ;
    END
  END b[93]
  PIN b[94]
    DIRECTION OUTPUT ;
    USE SIGNAL ;
    PORT
      LAYER M4 ;
        RECT  0 13.968 0.084 13.992 ;
    END
  END b[94]
  PIN b[95]
    DIRECTION OUTPUT ;
    USE SIGNAL ;
    PORT
      LAYER M4 ;
        RECT  0 14.064 0.084 14.088 ;
    END
  END b[95]
  PIN b[96]
    DIRECTION OUTPUT ;
    USE SIGNAL ;
    PORT
      LAYER M4 ;
        RECT  0 14.16 0.084 14.184 ;
    END
  END b[96]
  PIN b[97]
    DIRECTION OUTPUT ;
    USE SIGNAL ;
    PORT
      LAYER M4 ;
        RECT  0 14.256 0.084 14.28 ;
    END
  END b[97]
  PIN b[98]
    DIRECTION OUTPUT ;
    USE SIGNAL ;
    PORT
      LAYER M4 ;
        RECT  0 14.352 0.084 14.376 ;
    END
  END b[98]
  PIN b[99]
    DIRECTION OUTPUT ;
    USE SIGNAL ;
    PORT
      LAYER M4 ;
        RECT  0 14.448 0.084 14.472 ;
    END
  END b[99]
  PIN b[9]
    DIRECTION OUTPUT ;
    USE SIGNAL ;
    PORT
      LAYER M4 ;
        RECT  0 21.168 0.084 21.192 ;
    END
  END b[9]
  PIN ck
    DIRECTION INPUT ;
    USE SIGNAL ;
    PORT
      LAYER M3 ;
        RECT  27.252 30.179 27.27 30.216 ;
    END
  END ck
  PIN ck_o
    DIRECTION OUTPUT ;
    USE SIGNAL ;
    PORT
      LAYER M3 ;
        RECT  27.324 30.179 27.342 30.216 ;
    END
  END ck_o
  PIN eb
    DIRECTION OUTPUT ;
    USE SIGNAL ;
    PORT
      LAYER M4 ;
        RECT  0 10.992 0.084 11.016 ;
    END
  END eb
  PIN en
    DIRECTION INPUT ;
    USE SIGNAL ;
    PORT
      LAYER M3 ;
        RECT  27.396 30.179 27.414 30.216 ;
    END
  END en
  PIN VDD
    DIRECTION INOUT ;
    USE POWER ;
    PORT
      LAYER M5 ;
        RECT  61.992 2.151 62.112 27.833 ;
        RECT  59.292 2.151 59.412 27.833 ;
        RECT  56.592 2.151 56.712 27.833 ;
        RECT  53.892 2.151 54.012 27.833 ;
        RECT  51.192 2.151 51.312 27.833 ;
        RECT  48.492 2.151 48.612 27.833 ;
        RECT  45.792 2.151 45.912 27.833 ;
        RECT  43.092 2.151 43.212 27.833 ;
        RECT  40.392 2.151 40.512 27.833 ;
        RECT  37.692 2.151 37.812 27.833 ;
        RECT  34.992 2.151 35.112 27.833 ;
        RECT  32.292 2.151 32.412 27.833 ;
        RECT  29.592 2.151 29.712 27.833 ;
        RECT  26.892 2.151 27.012 27.833 ;
        RECT  24.192 2.151 24.312 27.833 ;
        RECT  21.492 2.151 21.612 27.833 ;
        RECT  18.792 2.151 18.912 27.833 ;
        RECT  16.092 2.151 16.212 27.833 ;
        RECT  13.392 2.151 13.512 27.833 ;
        RECT  10.692 2.151 10.812 27.833 ;
        RECT  7.992 2.151 8.112 27.833 ;
        RECT  5.292 2.151 5.412 27.833 ;
        RECT  2.592 2.151 2.712 27.833 ;
    END
  END VDD
  PIN VSS
    DIRECTION INOUT ;
    USE GROUND ;
    PORT
      LAYER M5 ;
        RECT  61.8 2.137 61.92 27.819 ;
        RECT  59.1 2.137 59.22 27.819 ;
        RECT  56.4 2.137 56.52 27.819 ;
        RECT  53.7 2.137 53.82 27.819 ;
        RECT  51 2.137 51.12 27.819 ;
        RECT  48.3 2.137 48.42 27.819 ;
        RECT  45.6 2.137 45.72 27.819 ;
        RECT  42.9 2.137 43.02 27.819 ;
        RECT  40.2 2.137 40.32 27.819 ;
        RECT  37.5 2.137 37.62 27.819 ;
        RECT  34.8 2.137 34.92 27.819 ;
        RECT  32.1 2.137 32.22 27.819 ;
        RECT  29.4 2.137 29.52 27.819 ;
        RECT  26.7 2.137 26.82 27.819 ;
        RECT  24 2.137 24.12 27.819 ;
        RECT  21.3 2.137 21.42 27.819 ;
        RECT  18.6 2.137 18.72 27.819 ;
        RECT  15.9 2.137 16.02 27.819 ;
        RECT  13.2 2.137 13.32 27.819 ;
        RECT  10.5 2.137 10.62 27.819 ;
        RECT  7.8 2.137 7.92 27.819 ;
        RECT  5.1 2.137 5.22 27.819 ;
        RECT  2.4 2.137 2.52 27.819 ;
    END
  END VSS
  # OT_OBS_CLOSED layer=M5 d_um=1.536 added=37
  OBS
    LAYER RVTN ;
     RECT  2.16 2.16 62.586 2.295 ;
     RECT  2.16 2.565 62.586 2.835 ;
     RECT  2.16 3.105 62.586 3.375 ;
     RECT  2.16 3.645 62.586 3.915 ;
     RECT  2.16 4.185 62.586 4.455 ;
     RECT  2.16 4.725 62.586 4.995 ;
     RECT  2.16 5.265 62.586 5.535 ;
     RECT  2.16 5.805 62.586 6.075 ;
     RECT  2.16 6.345 62.586 6.615 ;
     RECT  2.16 6.885 62.586 7.155 ;
     RECT  2.16 7.425 62.586 7.695 ;
     RECT  2.16 7.965 62.586 8.235 ;
     RECT  2.16 8.505 62.586 8.775 ;
     RECT  2.16 9.045 62.586 9.315 ;
     RECT  2.16 9.585 62.586 9.855 ;
     RECT  2.16 10.125 62.586 10.395 ;
     RECT  2.16 10.665 62.586 10.935 ;
     RECT  2.16 11.205 62.586 11.475 ;
     RECT  2.16 11.745 62.586 12.015 ;
     RECT  2.16 12.285 62.586 12.555 ;
     RECT  2.16 12.825 62.586 13.095 ;
     RECT  2.16 13.365 62.586 13.635 ;
     RECT  2.16 13.905 62.586 14.175 ;
     RECT  2.16 14.445 62.586 14.715 ;
     RECT  2.16 14.985 62.586 15.255 ;
     RECT  2.16 15.525 62.586 15.795 ;
     RECT  2.16 16.065 62.586 16.335 ;
     RECT  2.16 16.605 62.586 16.875 ;
     RECT  2.16 17.145 62.586 17.415 ;
     RECT  2.16 17.685 62.586 17.955 ;
     RECT  2.16 18.225 62.586 18.495 ;
     RECT  2.16 18.765 62.586 19.035 ;
     RECT  2.16 19.305 62.586 19.575 ;
     RECT  2.16 19.845 62.586 20.115 ;
     RECT  2.16 20.385 62.586 20.655 ;
     RECT  2.16 20.925 62.586 21.195 ;
     RECT  2.16 21.465 62.586 21.735 ;
     RECT  2.16 22.005 62.586 22.275 ;
     RECT  2.16 22.545 62.586 22.815 ;
     RECT  2.16 23.085 62.586 23.355 ;
     RECT  2.16 23.625 62.586 23.895 ;
     RECT  2.16 24.165 62.586 24.435 ;
     RECT  2.16 24.705 62.586 24.975 ;
     RECT  2.16 25.245 62.586 25.515 ;
     RECT  2.16 25.785 62.586 26.055 ;
     RECT  2.16 26.325 62.586 26.595 ;
     RECT  2.16 26.865 62.586 27.135 ;
     RECT  2.16 27.405 62.586 27.675 ;
    LAYER RVTP ;
     RECT  2.16 2.295 62.586 2.565 ;
     RECT  2.16 2.835 62.586 3.105 ;
     RECT  2.16 3.375 62.586 3.645 ;
     RECT  2.16 3.915 62.586 4.185 ;
     RECT  2.16 4.455 62.586 4.725 ;
     RECT  2.16 4.995 62.586 5.265 ;
     RECT  2.16 5.535 62.586 5.805 ;
     RECT  2.16 6.075 62.586 6.345 ;
     RECT  2.16 6.615 62.586 6.885 ;
     RECT  2.16 7.155 62.586 7.425 ;
     RECT  2.16 7.695 62.586 7.965 ;
     RECT  2.16 8.235 62.586 8.505 ;
     RECT  2.16 8.775 62.586 9.045 ;
     RECT  2.16 9.315 62.586 9.585 ;
     RECT  2.16 9.855 62.586 10.125 ;
     RECT  2.16 10.395 62.586 10.665 ;
     RECT  2.16 10.935 62.586 11.205 ;
     RECT  2.16 11.475 62.586 11.745 ;
     RECT  2.16 12.015 62.586 12.285 ;
     RECT  2.16 12.555 62.586 12.825 ;
     RECT  2.16 13.095 62.586 13.365 ;
     RECT  2.16 13.635 62.586 13.905 ;
     RECT  2.16 14.175 62.586 14.445 ;
     RECT  2.16 14.715 62.586 14.985 ;
     RECT  2.16 15.255 62.586 15.525 ;
     RECT  2.16 15.795 62.586 16.065 ;
     RECT  2.16 16.335 62.586 16.605 ;
     RECT  2.16 16.875 62.586 17.145 ;
     RECT  2.16 17.415 62.586 17.685 ;
     RECT  2.16 17.955 62.586 18.225 ;
     RECT  2.16 18.495 62.586 18.765 ;
     RECT  2.16 19.035 62.586 19.305 ;
     RECT  2.16 19.575 62.586 19.845 ;
     RECT  2.16 20.115 62.586 20.385 ;
     RECT  2.16 20.655 62.586 20.925 ;
     RECT  2.16 21.195 62.586 21.465 ;
     RECT  2.16 21.735 62.586 22.005 ;
     RECT  2.16 22.275 62.586 22.545 ;
     RECT  2.16 22.815 62.586 23.085 ;
     RECT  2.16 23.355 62.586 23.625 ;
     RECT  2.16 23.895 62.586 24.165 ;
     RECT  2.16 24.435 62.586 24.705 ;
     RECT  2.16 24.975 62.586 25.245 ;
     RECT  2.16 25.515 62.586 25.785 ;
     RECT  2.16 26.055 62.586 26.325 ;
     RECT  2.16 26.595 62.586 26.865 ;
     RECT  2.16 27.135 62.586 27.405 ;
     RECT  2.16 27.675 62.586 27.81 ;
    LAYER M1 ;
     RECT  2.16 2.151 62.586 27.819 ;
    LAYER M2 ;
     RECT  0.031 17.19 0.103 17.208 ;
     RECT  0.067 14.256 0.167 14.274 ;
     RECT  0.067 7.704 0.175 7.722 ;
     RECT  0.103 8.478 0.175 8.496 ;
     RECT  0.103 17.082 0.175 17.208 ;
     RECT  0.175 7.704 0.211 8.496 ;
     RECT  0.139 13.374 0.211 13.392 ;
     RECT  0.211 13.266 0.239 13.392 ;
     RECT  0.239 13.266 0.311 13.284 ;
     RECT  0.211 7.668 0.391 8.496 ;
     RECT  0.175 17.082 0.427 17.244 ;
     RECT  0.139 19.656 0.427 19.674 ;
     RECT  0.103 21.591 0.427 21.609 ;
     RECT  0.355 14.526 0.455 14.544 ;
     RECT  0.427 19.548 0.463 19.674 ;
     RECT  0.463 19.548 0.499 19.872 ;
     RECT  0.427 21.591 0.499 22.068 ;
     RECT  0.427 22.896 0.499 22.914 ;
     RECT  0.499 21.591 0.527 22.914 ;
     RECT  0.031 10.602 0.535 10.62 ;
     RECT  0.139 11.754 0.535 12.474 ;
     RECT  0.499 14.688 0.535 15.894 ;
     RECT  0.427 17.082 0.535 17.478 ;
     RECT  0.499 18.621 0.535 20.304 ;
     RECT  0.527 21.591 0.535 22.536 ;
     RECT  0.535 14.688 0.599 20.376 ;
     RECT  0.391 7.668 2.16 8.532 ;
     RECT  0.535 10.602 2.16 12.474 ;
     RECT  0.599 14.688 2.16 15.282 ;
     RECT  0.599 16.308 2.16 20.376 ;
     RECT  0.535 21.546 2.16 22.536 ;
     RECT  27.391 30.15 27.491 30.168 ;
     RECT  2.16 2.151 62.586 27.819 ;
     RECT  62.586 6.624 62.627 19.296 ;
     RECT  62.627 6.624 62.771 19.062 ;
     RECT  62.771 6.858 63.311 8.064 ;
     RECT  62.771 9.054 63.311 19.062 ;
     RECT  63.311 15.066 63.347 17.1 ;
     RECT  63.311 17.928 63.347 19.062 ;
     RECT  63.311 10.638 63.419 13.734 ;
     RECT  63.419 11.016 63.815 13.734 ;
     RECT  63.311 9.054 63.851 9.576 ;
     RECT  63.311 6.858 63.887 7.416 ;
     RECT  63.851 9.09 63.887 9.576 ;
     RECT  63.815 11.646 63.887 13.734 ;
     RECT  63.347 15.066 63.887 15.084 ;
     RECT  63.347 15.876 63.887 17.064 ;
     RECT  63.347 18.972 63.887 19.062 ;
     RECT  63.887 6.858 63.923 6.876 ;
     RECT  63.887 11.646 63.923 13.392 ;
     RECT  63.887 16.074 63.923 16.938 ;
     RECT  63.887 18.972 63.923 18.99 ;
     RECT  63.923 12.258 63.959 12.582 ;
     RECT  63.923 13.374 63.959 13.392 ;
     RECT  63.923 16.344 63.959 16.56 ;
     RECT  64.651 7.866 64.751 7.884 ;
    LAYER M3 ;
     RECT  2.415 2.143 2.505 2.413 ;
     RECT  5.115 2.143 5.205 2.413 ;
     RECT  7.815 2.143 7.905 2.413 ;
     RECT  10.515 2.143 10.605 2.413 ;
     RECT  13.215 2.143 13.305 2.413 ;
     RECT  15.915 2.143 16.005 2.413 ;
     RECT  18.615 2.143 18.705 2.413 ;
     RECT  21.315 2.143 21.405 2.413 ;
     RECT  24.015 2.143 24.105 2.413 ;
     RECT  26.715 2.143 26.805 2.413 ;
     RECT  29.415 2.143 29.505 2.413 ;
     RECT  32.115 2.143 32.205 2.413 ;
     RECT  34.815 2.143 34.905 2.413 ;
     RECT  37.515 2.143 37.605 2.413 ;
     RECT  40.215 2.143 40.305 2.413 ;
     RECT  42.915 2.143 43.005 2.413 ;
     RECT  45.615 2.143 45.705 2.413 ;
     RECT  48.315 2.143 48.405 2.413 ;
     RECT  51.015 2.143 51.105 2.413 ;
     RECT  53.715 2.143 53.805 2.413 ;
     RECT  56.415 2.143 56.505 2.413 ;
     RECT  59.115 2.143 59.205 2.413 ;
     RECT  61.815 2.143 61.905 2.413 ;
     RECT  59.115 2.413 59.397 6.619 ;
     RECT  61.815 2.413 62.097 6.619 ;
     RECT  61.815 6.619 62.766 6.691 ;
     RECT  57.924 6.619 57.942 6.808 ;
     RECT  61.38 6.691 62.766 6.853 ;
     RECT  32.115 2.413 32.397 6.889 ;
     RECT  60.804 6.853 62.766 6.925 ;
     RECT  63.9 6.853 63.918 6.925 ;
     RECT  54.792 6.889 54.81 6.961 ;
     RECT  58.716 6.619 59.397 6.961 ;
     RECT  60.804 6.925 63.918 6.961 ;
     RECT  29.415 2.413 29.697 7.051 ;
     RECT  56.415 2.413 56.697 7.357 ;
     RECT  57.744 6.808 57.942 7.357 ;
     RECT  32.004 6.889 32.397 7.393 ;
     RECT  54.72 6.961 54.81 7.465 ;
     RECT  56.376 7.357 57.942 7.465 ;
     RECT  58.716 6.961 63.918 7.465 ;
     RECT  56.376 7.465 63.918 7.469 ;
     RECT  29.415 7.051 29.934 7.501 ;
     RECT  56.376 7.469 63.342 7.565 ;
     RECT  29.415 7.501 29.97 7.591 ;
     RECT  30.78 7.087 30.798 7.591 ;
     RECT  31.68 7.393 32.397 7.591 ;
     RECT  54.72 7.465 54.846 7.619 ;
     RECT  34.815 2.413 35.097 7.627 ;
     RECT  56.376 7.565 63.306 7.655 ;
     RECT  29.415 7.591 30.042 7.663 ;
     RECT  30.78 7.591 32.397 7.663 ;
     RECT  0.216 7.663 0.234 7.699 ;
     RECT  28.368 7.429 28.386 7.699 ;
     RECT  29.415 7.663 32.397 7.699 ;
     RECT  34.74 7.627 35.097 7.727 ;
     RECT  0.072 7.699 0.234 7.861 ;
     RECT  64.656 7.819 64.674 7.861 ;
     RECT  64.656 7.861 64.746 7.889 ;
     RECT  56.376 7.655 61.038 7.897 ;
     RECT  64.728 7.889 64.746 7.901 ;
     RECT  26.715 2.413 26.997 7.969 ;
     RECT  56.232 7.897 61.038 7.997 ;
     RECT  54.792 7.619 54.846 8.041 ;
     RECT  0.072 7.861 0.27 8.239 ;
     RECT  28.368 7.699 32.397 8.275 ;
     RECT  0.072 8.239 0.342 8.311 ;
     RECT  61.815 7.655 63.306 8.333 ;
     RECT  56.232 7.997 57.762 8.437 ;
     RECT  58.5 7.997 61.038 8.437 ;
     RECT  61.815 8.333 62.766 8.437 ;
     RECT  58.5 8.437 62.766 8.477 ;
     RECT  54.792 8.041 54.882 8.491 ;
     RECT  0.072 8.311 0.378 8.509 ;
     RECT  53.715 2.413 53.997 8.509 ;
     RECT  54.792 8.491 55.278 8.509 ;
     RECT  28.296 8.275 32.397 8.545 ;
     RECT  51.015 2.413 51.297 8.545 ;
     RECT  50.796 8.545 51.297 8.581 ;
     RECT  28.188 8.545 32.397 8.609 ;
     RECT  26.715 7.969 27.09 8.671 ;
     RECT  28.188 8.609 28.494 8.671 ;
     RECT  33.3 8.581 33.318 8.671 ;
     RECT  53.715 8.509 55.278 8.699 ;
     RECT  33.3 8.671 33.39 8.707 ;
     RECT  56.088 8.437 57.762 8.743 ;
     RECT  58.5 8.477 60.642 8.743 ;
     RECT  33.3 8.707 33.462 8.851 ;
     RECT  54.864 8.699 55.278 8.879 ;
     RECT  50.724 8.581 51.297 8.969 ;
     RECT  33.3 8.851 34.002 8.977 ;
     RECT  34.815 7.727 35.097 8.977 ;
     RECT  61.416 8.477 62.766 9.067 ;
     RECT  63.828 8.779 63.882 9.067 ;
     RECT  26.715 8.671 28.494 9.085 ;
     RECT  55.26 8.879 55.278 9.085 ;
     RECT  33.3 8.977 35.097 9.113 ;
     RECT  29.415 8.609 32.397 9.211 ;
     RECT  55.26 9.085 55.314 9.211 ;
     RECT  56.088 8.743 60.642 9.211 ;
     RECT  33.3 9.113 34.074 9.239 ;
     RECT  55.26 9.211 60.642 9.239 ;
     RECT  55.296 9.239 60.642 9.311 ;
     RECT  33.3 9.239 33.966 9.391 ;
     RECT  55.332 9.311 60.642 9.391 ;
     RECT  61.416 9.067 63.882 9.391 ;
     RECT  33.228 9.391 33.966 9.509 ;
     RECT  55.332 9.391 63.882 9.587 ;
     RECT  55.332 9.587 63.342 9.677 ;
     RECT  29.415 9.211 32.49 9.751 ;
     RECT  51.015 8.969 51.297 9.823 ;
     RECT  53.715 8.699 53.997 9.823 ;
     RECT  53.028 9.823 53.997 10.049 ;
     RECT  55.332 9.677 57.366 10.049 ;
     RECT  55.332 10.049 57.258 10.201 ;
     RECT  29.415 9.751 32.634 10.291 ;
     RECT  33.372 9.509 33.966 10.291 ;
     RECT  29.415 10.291 33.966 10.327 ;
     RECT  34.815 9.113 35.097 10.327 ;
     RECT  58.14 9.677 63.342 10.411 ;
     RECT  29.415 10.327 35.097 10.427 ;
     RECT  58.14 10.411 63.414 10.459 ;
     RECT  51.015 9.823 51.354 10.463 ;
     RECT  58.104 10.459 63.414 10.507 ;
     RECT  0.072 8.509 0.414 10.597 ;
     RECT  25.092 10.363 25.11 10.597 ;
     RECT  2.415 2.413 2.697 10.633 ;
     RECT  55.296 10.201 57.258 10.741 ;
     RECT  25.092 10.597 25.182 10.769 ;
     RECT  58.104 10.507 63.81 10.831 ;
     RECT  26.532 9.085 28.494 10.867 ;
     RECT  29.415 10.427 33.966 10.867 ;
     RECT  54.972 10.741 57.258 10.939 ;
     RECT  58.032 10.831 63.81 10.939 ;
     RECT  54.972 10.939 63.81 10.967 ;
     RECT  53.064 10.049 53.997 11.011 ;
     RECT  2.415 10.633 3.186 11.101 ;
     RECT  5.115 2.413 5.397 11.101 ;
     RECT  0.036 10.597 0.414 11.209 ;
     RECT  10.515 2.413 10.797 11.209 ;
     RECT  6.876 11.209 6.894 11.227 ;
     RECT  14.868 11.209 14.886 11.227 ;
     RECT  2.415 11.101 3.51 11.245 ;
     RECT  4.5 11.101 5.397 11.245 ;
     RECT  2.415 11.245 5.397 11.272 ;
     RECT  10.515 11.209 10.89 11.272 ;
     RECT  13.215 2.413 13.497 11.272 ;
     RECT  15.915 2.413 16.197 11.272 ;
     RECT  21.315 2.413 21.597 11.272 ;
     RECT  24.015 2.413 24.297 11.272 ;
     RECT  6.84 11.227 6.894 11.309 ;
     RECT  10.404 11.272 10.89 11.309 ;
     RECT  15.804 11.272 16.197 11.309 ;
     RECT  23.904 11.272 24.297 11.309 ;
     RECT  2.304 11.272 5.397 11.399 ;
     RECT  26.532 10.867 33.966 11.443 ;
     RECT  34.74 10.427 35.097 11.443 ;
     RECT  0.036 11.209 0.558 11.515 ;
     RECT  2.304 11.399 3.978 11.543 ;
     RECT  63.792 10.967 63.81 11.563 ;
     RECT  0.036 11.515 0.63 11.579 ;
     RECT  0.036 11.579 0.558 11.597 ;
     RECT  2.304 11.543 3.258 11.597 ;
     RECT  53.028 11.011 53.997 11.641 ;
     RECT  63.792 11.563 63.882 11.641 ;
     RECT  22.824 11.209 22.842 11.659 ;
     RECT  22.824 11.659 22.986 11.693 ;
     RECT  53.028 11.641 54.054 11.693 ;
     RECT  10.515 11.309 10.818 11.705 ;
     RECT  53.028 11.693 53.997 11.707 ;
     RECT  26.532 11.443 35.097 11.713 ;
     RECT  38.772 11.713 38.79 11.785 ;
     RECT  14.832 11.227 14.886 11.803 ;
     RECT  52.704 11.707 53.997 11.813 ;
     RECT  6.84 11.309 6.858 11.837 ;
     RECT  5.004 11.399 5.397 11.849 ;
     RECT  13.104 11.272 13.497 11.849 ;
     RECT  21.204 11.272 21.597 11.849 ;
     RECT  2.304 11.597 3.186 11.885 ;
     RECT  38.664 11.785 38.79 11.939 ;
     RECT  26.532 11.713 35.154 11.947 ;
     RECT  14.832 11.803 14.958 11.981 ;
     RECT  26.532 11.947 35.946 11.984 ;
     RECT  37.515 2.413 37.797 12.187 ;
     RECT  45.615 2.413 45.897 12.187 ;
     RECT  54.972 10.967 62.766 12.235 ;
     RECT  63.792 11.641 63.918 12.235 ;
     RECT  54.972 12.235 63.918 12.253 ;
     RECT  37.515 12.187 37.89 12.317 ;
     RECT  38.736 11.939 38.79 12.317 ;
     RECT  45.615 12.187 45.99 12.317 ;
     RECT  46.764 12.187 46.782 12.317 ;
     RECT  38.736 12.317 38.754 12.389 ;
     RECT  22.896 11.693 22.986 12.571 ;
     RECT  5.115 11.849 5.397 12.619 ;
     RECT  15.915 11.309 16.197 12.619 ;
     RECT  49.608 12.253 49.626 12.623 ;
     RECT  24.015 11.309 24.297 12.631 ;
     RECT  42.915 2.413 43.197 12.631 ;
     RECT  45.615 12.317 45.897 12.631 ;
     RECT  51.015 10.463 51.297 12.631 ;
     RECT  5.115 12.619 5.49 12.659 ;
     RECT  24.015 12.631 24.39 12.701 ;
     RECT  7.815 2.413 8.097 12.715 ;
     RECT  50.796 12.631 51.297 12.721 ;
     RECT  53.028 11.813 53.997 12.721 ;
     RECT  22.824 12.571 22.986 12.749 ;
     RECT  7.815 12.715 8.19 12.755 ;
     RECT  15.915 12.619 16.29 12.755 ;
     RECT  10.515 11.705 10.797 12.757 ;
     RECT  45.36 12.631 45.897 12.757 ;
     RECT  42.768 12.631 43.197 12.758 ;
     RECT  44.1 12.721 44.118 12.763 ;
     RECT  22.896 12.749 22.986 12.797 ;
     RECT  18.615 2.413 18.897 12.856 ;
     RECT  42.84 12.758 43.197 12.857 ;
     RECT  2.415 11.885 3.186 12.859 ;
     RECT  6.84 12.715 6.858 12.859 ;
     RECT  10.515 12.757 10.818 12.893 ;
     RECT  18.576 12.856 18.897 12.893 ;
     RECT  22.968 12.797 22.986 12.893 ;
     RECT  2.34 12.859 3.186 12.991 ;
     RECT  5.115 12.659 5.397 12.991 ;
     RECT  13.215 11.849 13.497 12.991 ;
     RECT  21.315 11.849 21.597 12.991 ;
     RECT  43.992 12.763 44.118 13.019 ;
     RECT  6.84 12.859 6.966 13.037 ;
     RECT  14.94 12.859 14.958 13.037 ;
     RECT  52.308 12.721 53.997 13.085 ;
     RECT  25.092 13.051 25.11 13.099 ;
     RECT  26.532 11.984 35.91 13.135 ;
     RECT  0.036 11.597 0.414 13.195 ;
     RECT  26.532 13.135 35.946 13.289 ;
     RECT  0.036 13.195 0.45 13.325 ;
     RECT  25.092 13.099 25.182 13.397 ;
     RECT  54.972 12.253 63.954 13.469 ;
     RECT  45.216 12.757 45.897 13.531 ;
     RECT  25.164 13.397 25.182 13.559 ;
     RECT  50.724 12.721 51.297 13.559 ;
     RECT  45.216 13.531 46.782 13.603 ;
     RECT  63.864 13.469 63.954 13.613 ;
     RECT  45 13.603 46.782 13.661 ;
     RECT  50.76 13.559 51.297 13.661 ;
     RECT  26.532 13.289 35.154 13.867 ;
     RECT  45.288 13.661 46.566 13.901 ;
     RECT  26.496 13.867 35.154 13.915 ;
     RECT  6.84 13.037 6.858 13.997 ;
     RECT  14.832 13.531 14.85 13.997 ;
     RECT  2.304 12.991 3.186 14.009 ;
     RECT  5.004 12.991 5.397 14.009 ;
     RECT  13.104 12.991 13.497 14.009 ;
     RECT  21.204 12.991 21.597 14.009 ;
     RECT  35.928 13.289 35.946 14.099 ;
     RECT  26.388 13.915 35.154 14.155 ;
     RECT  22.896 13.963 22.914 14.189 ;
     RECT  45.615 13.901 46.566 14.189 ;
     RECT  45.615 14.189 46.422 14.237 ;
     RECT  54.972 13.469 62.766 14.347 ;
     RECT  63.864 13.613 63.882 14.347 ;
     RECT  26.244 14.155 35.154 14.369 ;
     RECT  26.496 14.369 35.154 14.485 ;
     RECT  0.036 13.325 0.414 14.491 ;
     RECT  26.496 14.485 35.442 14.549 ;
     RECT  0.036 14.491 0.45 14.683 ;
     RECT  26.532 14.549 35.442 14.909 ;
     RECT  51.015 13.661 51.297 14.917 ;
     RECT  50.724 14.917 51.297 15.017 ;
     RECT  38.736 14.917 38.754 15.089 ;
     RECT  2.34 14.009 3.186 15.115 ;
     RECT  5.115 14.009 5.397 15.151 ;
     RECT  13.215 14.009 13.497 15.151 ;
     RECT  21.315 14.009 21.597 15.151 ;
     RECT  25.632 14.791 25.65 15.331 ;
     RECT  26.532 14.909 35.154 15.359 ;
     RECT  51.015 15.017 51.297 15.493 ;
     RECT  25.092 15.331 25.65 15.533 ;
     RECT  26.532 15.359 27.702 15.581 ;
     RECT  22.896 15.547 22.914 15.595 ;
     RECT  6.84 15.163 6.858 15.691 ;
     RECT  15.915 12.755 16.197 15.691 ;
     RECT  26.532 15.581 27.378 15.719 ;
     RECT  22.824 15.595 22.914 15.725 ;
     RECT  15.804 15.691 16.197 15.728 ;
     RECT  26.532 15.719 26.997 15.755 ;
     RECT  54.972 14.347 63.882 15.791 ;
     RECT  6.84 15.691 6.93 15.821 ;
     RECT  0.036 14.683 0.558 15.835 ;
     RECT  28.476 15.359 35.154 15.869 ;
     RECT  56.415 15.791 63.882 15.883 ;
     RECT  0.036 15.835 0.594 15.899 ;
     RECT  54.972 15.791 55.674 15.899 ;
     RECT  25.2 15.533 25.65 16.013 ;
     RECT  51.015 15.493 51.354 16.133 ;
     RECT  6.84 15.821 6.858 16.157 ;
     RECT  5.004 15.151 5.397 16.169 ;
     RECT  13.104 15.151 13.497 16.169 ;
     RECT  21.204 15.151 21.597 16.169 ;
     RECT  2.304 15.115 3.186 16.205 ;
     RECT  21.315 16.169 21.597 16.315 ;
     RECT  56.415 15.883 63.954 16.367 ;
     RECT  5.115 16.169 5.397 16.501 ;
     RECT  63.252 16.367 63.954 16.565 ;
     RECT  54.972 15.899 55.314 16.747 ;
     RECT  56.415 16.367 62.334 16.747 ;
     RECT  28.512 15.869 35.154 16.771 ;
     RECT  48.315 2.413 48.597 16.771 ;
     RECT  54.972 16.747 55.35 16.771 ;
     RECT  48.315 16.771 49.05 16.795 ;
     RECT  51.015 16.133 51.297 16.795 ;
     RECT  28.476 16.771 35.154 16.799 ;
     RECT  53.028 13.085 53.997 16.799 ;
     RECT  47.916 16.795 49.05 16.829 ;
     RECT  47.916 16.829 48.597 16.835 ;
     RECT  5.115 16.501 5.49 16.879 ;
     RECT  63.252 16.565 63.918 16.943 ;
     RECT  21.315 16.315 21.69 16.973 ;
     RECT  5.115 16.879 5.562 16.979 ;
     RECT  25.092 16.303 25.11 16.979 ;
     RECT  48.024 16.835 48.597 17.069 ;
     RECT  63.252 16.943 63.882 17.069 ;
     RECT  54.972 16.771 55.422 17.077 ;
     RECT  10.515 12.893 10.797 17.083 ;
     RECT  63.252 17.069 63.342 17.105 ;
     RECT  54.972 17.077 55.458 17.113 ;
     RECT  56.196 16.747 62.334 17.113 ;
     RECT  28.476 16.799 33.39 17.149 ;
     RECT  54.972 17.113 62.334 17.185 ;
     RECT  0.036 15.899 0.558 17.213 ;
     RECT  54.72 17.185 62.334 17.221 ;
     RECT  63.252 17.105 63.306 17.221 ;
     RECT  2.34 16.205 3.186 17.311 ;
     RECT  5.115 16.979 5.397 17.311 ;
     RECT  13.215 16.169 13.497 17.311 ;
     RECT  21.315 16.973 21.597 17.311 ;
     RECT  26.715 15.755 26.997 17.311 ;
     RECT  6.84 17.083 6.858 17.323 ;
     RECT  54.72 17.221 63.306 17.411 ;
     RECT  6.84 17.323 6.966 17.453 ;
     RECT  10.515 17.083 10.818 17.453 ;
     RECT  26.676 17.311 26.997 17.491 ;
     RECT  27.828 17.149 33.39 17.491 ;
     RECT  22.824 15.725 22.842 17.659 ;
     RECT  26.676 17.491 33.39 17.693 ;
     RECT  26.676 17.693 27.486 17.725 ;
     RECT  22.824 17.659 22.914 17.789 ;
     RECT  50.724 16.795 51.297 17.789 ;
     RECT  54.972 17.411 63.306 17.923 ;
     RECT  50.796 17.789 51.297 17.951 ;
     RECT  53.715 16.799 53.997 17.995 ;
     RECT  26.64 17.725 27.486 18.023 ;
     RECT  54.972 17.923 63.342 18.059 ;
     RECT  54.972 18.059 55.35 18.221 ;
     RECT  53.715 17.995 54.198 18.265 ;
     RECT  54.972 18.221 55.206 18.265 ;
     RECT  2.304 17.311 3.186 18.329 ;
     RECT  5.004 17.311 5.397 18.329 ;
     RECT  13.104 17.311 13.497 18.329 ;
     RECT  21.204 17.311 21.597 18.329 ;
     RECT  6.84 17.453 6.858 18.461 ;
     RECT  22.824 17.789 22.842 18.461 ;
     RECT  28.476 17.693 33.39 18.463 ;
     RECT  34.128 16.799 35.154 18.463 ;
     RECT  14.832 15.163 14.85 18.475 ;
     RECT  21.315 18.329 21.597 18.475 ;
     RECT  0.108 17.213 0.558 18.523 ;
     RECT  0.108 18.523 0.63 18.535 ;
     RECT  28.476 18.463 35.154 18.571 ;
     RECT  53.715 18.265 55.206 18.599 ;
     RECT  0.108 18.535 1.134 18.644 ;
     RECT  14.832 18.475 15.03 18.653 ;
     RECT  5.115 18.329 5.397 18.661 ;
     RECT  56.124 18.059 63.342 18.689 ;
     RECT  5.115 18.661 5.49 18.701 ;
     RECT  61.815 18.689 63.342 18.701 ;
     RECT  56.124 18.689 60.642 18.761 ;
     RECT  26.64 18.023 27.054 18.769 ;
     RECT  27.9 18.571 35.154 18.769 ;
     RECT  14.832 18.653 14.958 18.797 ;
     RECT  21.315 18.475 21.798 18.797 ;
     RECT  22.896 18.667 22.914 18.797 ;
     RECT  56.124 18.761 57.582 18.833 ;
     RECT  47.232 18.811 47.25 18.955 ;
     RECT  54.72 18.599 55.206 18.955 ;
     RECT  56.124 18.833 57.546 18.955 ;
     RECT  63.864 18.763 63.882 18.955 ;
     RECT  47.232 18.955 47.286 18.959 ;
     RECT  26.64 18.769 35.154 18.989 ;
     RECT  63.864 18.955 63.918 18.995 ;
     RECT  26.64 18.989 26.997 19.051 ;
     RECT  63.864 18.995 63.882 19.067 ;
     RECT  26.244 19.051 26.997 19.139 ;
     RECT  54.72 18.955 57.546 19.139 ;
     RECT  56.376 19.139 57.546 19.229 ;
     RECT  58.32 18.761 60.642 19.229 ;
     RECT  56.376 19.229 57.402 19.265 ;
     RECT  58.788 19.229 59.397 19.265 ;
     RECT  60.12 19.229 60.642 19.265 ;
     RECT  47.268 18.959 47.286 19.277 ;
     RECT  27.864 18.989 35.154 19.301 ;
     RECT  61.815 18.701 62.622 19.301 ;
     RECT  56.376 19.265 56.754 19.337 ;
     RECT  60.624 19.265 60.642 19.337 ;
     RECT  2.34 18.329 3.186 19.435 ;
     RECT  5.115 18.701 5.397 19.471 ;
     RECT  13.215 18.329 13.497 19.471 ;
     RECT  21.315 18.797 21.597 19.471 ;
     RECT  56.376 19.337 56.697 19.499 ;
     RECT  54.72 19.139 55.602 19.535 ;
     RECT  6.84 19.483 6.858 19.613 ;
     RECT  14.832 18.797 14.85 19.613 ;
     RECT  22.824 19.483 22.842 19.613 ;
     RECT  54.72 19.535 54.99 19.679 ;
     RECT  10.515 17.453 10.797 19.912 ;
     RECT  15.915 15.728 16.197 19.912 ;
     RECT  24.015 12.701 24.297 19.912 ;
     RECT  26.676 19.139 26.997 19.912 ;
     RECT  2.304 19.435 3.186 19.949 ;
     RECT  5.004 19.471 5.397 19.949 ;
     RECT  10.404 19.912 10.797 19.949 ;
     RECT  13.104 19.471 13.497 19.949 ;
     RECT  15.804 19.912 16.197 19.949 ;
     RECT  21.204 19.471 21.597 19.949 ;
     RECT  23.904 19.912 24.297 19.949 ;
     RECT  26.604 19.912 26.997 19.949 ;
     RECT  54.972 19.679 54.99 20.039 ;
     RECT  2.34 19.949 3.186 20.191 ;
     RECT  2.34 20.191 3.294 20.309 ;
     RECT  28.044 19.301 35.154 20.345 ;
     RECT  28.044 20.345 33.39 20.461 ;
     RECT  0.108 18.644 0.558 20.525 ;
     RECT  0.504 20.525 0.558 20.683 ;
     RECT  0.504 20.683 0.63 20.717 ;
     RECT  27.936 20.461 33.39 20.731 ;
     RECT  0.612 20.717 0.63 20.813 ;
     RECT  26.676 19.949 26.997 20.909 ;
     RECT  2.34 20.309 3.006 21.001 ;
     RECT  21.315 19.949 21.597 21.163 ;
     RECT  27.9 20.731 33.39 21.197 ;
     RECT  5.115 19.949 5.397 21.259 ;
     RECT  14.94 21.163 14.958 21.293 ;
     RECT  22.896 21.163 22.914 21.293 ;
     RECT  5.115 21.259 5.49 21.299 ;
     RECT  21.315 21.163 21.798 21.485 ;
     RECT  2.304 21.001 3.006 21.541 ;
     RECT  0.54 21.541 0.558 21.58 ;
     RECT  5.115 21.299 5.397 21.631 ;
     RECT  7.815 12.755 8.097 21.631 ;
     RECT  13.215 19.949 13.497 21.631 ;
     RECT  21.315 21.485 21.597 21.631 ;
     RECT  26.715 20.909 26.997 21.631 ;
     RECT  7.416 21.631 8.097 21.643 ;
     RECT  2.304 21.541 3.15 21.659 ;
     RECT  45.615 14.237 45.897 21.691 ;
     RECT  2.304 21.659 3.006 21.695 ;
     RECT  6.948 21.643 8.097 21.739 ;
     RECT  10.515 19.949 10.797 21.739 ;
     RECT  45.288 21.691 45.897 21.787 ;
     RECT  34.128 20.345 35.154 21.803 ;
     RECT  6.84 21.739 8.097 21.821 ;
     RECT  0.108 21.58 0.558 21.869 ;
     RECT  45.288 21.787 46.278 21.929 ;
     RECT  10.515 21.739 10.818 21.937 ;
     RECT  13.104 21.631 13.497 21.937 ;
     RECT  10.515 21.937 10.854 22.009 ;
     RECT  6.84 21.821 6.93 22.013 ;
     RECT  22.824 21.739 22.878 22.013 ;
     RECT  10.515 22.009 10.926 22.072 ;
     RECT  24.015 19.949 24.297 22.072 ;
     RECT  26.64 21.631 26.997 22.072 ;
     RECT  13.104 21.937 13.554 22.073 ;
     RECT  5.004 21.631 5.397 22.109 ;
     RECT  6.912 22.013 6.93 22.109 ;
     RECT  10.404 22.072 10.926 22.109 ;
     RECT  13.104 22.073 13.497 22.109 ;
     RECT  14.832 21.643 14.85 22.109 ;
     RECT  21.204 21.631 21.597 22.109 ;
     RECT  22.86 22.013 22.878 22.109 ;
     RECT  23.904 22.072 24.297 22.109 ;
     RECT  26.604 22.072 26.997 22.109 ;
     RECT  2.304 21.695 2.697 22.157 ;
     RECT  28.044 21.197 33.39 22.199 ;
     RECT  34.128 21.803 35.097 22.235 ;
     RECT  28.044 22.199 33.066 22.343 ;
     RECT  17.064 21.811 17.082 22.349 ;
     RECT  0.144 21.869 0.558 22.445 ;
     RECT  30.78 22.343 33.066 22.505 ;
     RECT  34.452 22.235 35.097 22.505 ;
     RECT  30.852 22.505 33.066 22.613 ;
     RECT  0.432 22.445 0.558 22.928 ;
     RECT  0.54 22.928 0.558 23.021 ;
     RECT  31.14 22.613 33.066 23.045 ;
     RECT  2.415 22.157 2.697 23.089 ;
     RECT  31.14 23.045 31.158 23.117 ;
     RECT  32.004 23.045 32.397 23.189 ;
     RECT  2.304 23.089 2.697 23.213 ;
     RECT  26.715 22.109 26.997 25.321 ;
     RECT  28.044 22.343 29.697 25.321 ;
     RECT  26.715 25.321 29.697 26.555 ;
     RECT  26.715 26.555 27.954 26.779 ;
     RECT  28.764 26.555 29.697 26.861 ;
     RECT  26.604 26.779 27.954 27.059 ;
     RECT  26.715 27.059 27.954 27.329 ;
     RECT  2.415 23.213 2.697 27.557 ;
     RECT  5.115 22.109 5.397 27.557 ;
     RECT  7.815 21.821 8.097 27.557 ;
     RECT  10.515 22.109 10.797 27.557 ;
     RECT  13.215 22.109 13.497 27.557 ;
     RECT  15.915 19.949 16.197 27.557 ;
     RECT  18.615 12.893 18.897 27.557 ;
     RECT  21.315 22.109 21.597 27.557 ;
     RECT  24.015 22.109 24.297 27.557 ;
     RECT  26.715 27.329 27.486 27.557 ;
     RECT  29.415 26.861 29.697 27.557 ;
     RECT  32.115 23.189 32.397 27.557 ;
     RECT  34.815 22.505 35.097 27.557 ;
     RECT  37.515 12.317 37.797 27.557 ;
     RECT  40.215 2.413 40.497 27.557 ;
     RECT  42.915 12.857 43.197 27.557 ;
     RECT  45.615 21.929 45.897 27.557 ;
     RECT  48.315 17.069 48.597 27.557 ;
     RECT  51.015 17.951 51.297 27.557 ;
     RECT  53.715 18.599 53.997 27.557 ;
     RECT  56.415 19.499 56.697 27.557 ;
     RECT  59.115 19.265 59.397 27.557 ;
     RECT  61.815 19.301 62.097 27.557 ;
     RECT  26.856 27.557 27.486 27.635 ;
     RECT  28.368 27.595 28.386 27.635 ;
     RECT  2.607 27.557 2.697 27.827 ;
     RECT  5.307 27.557 5.397 27.827 ;
     RECT  8.007 27.557 8.097 27.827 ;
     RECT  10.707 27.557 10.797 27.827 ;
     RECT  13.407 27.557 13.497 27.827 ;
     RECT  16.107 27.557 16.197 27.827 ;
     RECT  18.807 27.557 18.897 27.827 ;
     RECT  21.507 27.557 21.597 27.827 ;
     RECT  24.207 27.557 24.297 27.827 ;
     RECT  26.907 27.635 27.486 27.827 ;
     RECT  29.607 27.557 29.697 27.827 ;
     RECT  32.307 27.557 32.397 27.827 ;
     RECT  35.007 27.557 35.097 27.827 ;
     RECT  37.707 27.557 37.797 27.827 ;
     RECT  40.407 27.557 40.497 27.827 ;
     RECT  43.107 27.557 43.197 27.827 ;
     RECT  45.807 27.557 45.897 27.827 ;
     RECT  48.507 27.557 48.597 27.827 ;
     RECT  51.207 27.557 51.297 27.827 ;
     RECT  53.907 27.557 53.997 27.827 ;
     RECT  56.607 27.557 56.697 27.827 ;
     RECT  59.307 27.557 59.397 27.827 ;
     RECT  62.007 27.557 62.097 27.827 ;
     RECT  27.072 27.827 27.486 27.917 ;
     RECT  27.468 27.917 27.486 29.659 ;
     RECT  27.252 29.659 27.486 30.173 ;
     RECT  27.252 30.173 27.414 30.179 ;
     RECT  27.27 30.179 27.324 30.204 ;
     RECT  27.342 30.179 27.396 30.204 ;
    LAYER M4 ;
     RECT  0.084 10.992 2.408 11.016 ;
     RECT  0.06 11.016 2.408 11.088 ;
     RECT  0.084 11.088 2.408 11.112 ;
     RECT  0.06 11.112 2.408 11.184 ;
     RECT  0.084 11.184 2.408 11.208 ;
     RECT  0.06 11.208 2.408 11.28 ;
     RECT  0.084 11.28 2.408 11.304 ;
     RECT  0.06 11.304 2.408 11.376 ;
     RECT  0.084 11.376 2.408 11.4 ;
     RECT  0.06 11.4 2.408 11.472 ;
     RECT  0.084 11.472 2.408 11.496 ;
     RECT  0.06 11.496 2.408 11.568 ;
     RECT  0.084 11.568 2.408 11.592 ;
     RECT  0.06 11.592 2.408 11.664 ;
     RECT  0.084 11.664 2.408 11.688 ;
     RECT  0.06 11.688 2.408 11.76 ;
     RECT  0.084 11.76 2.408 11.784 ;
     RECT  0.06 11.784 2.408 11.856 ;
     RECT  0.084 11.856 2.408 11.88 ;
     RECT  0.06 11.88 2.408 11.952 ;
     RECT  0.084 11.952 2.408 11.976 ;
     RECT  0.06 11.976 2.408 12.048 ;
     RECT  0.084 12.048 2.408 12.072 ;
     RECT  0.06 12.072 2.408 12.144 ;
     RECT  0.084 12.144 2.408 12.168 ;
     RECT  0.06 12.168 2.408 12.24 ;
     RECT  0.084 12.24 2.408 12.264 ;
     RECT  0.06 12.264 2.408 12.336 ;
     RECT  0.084 12.336 2.408 12.36 ;
     RECT  0.06 12.36 2.408 12.432 ;
     RECT  0.084 12.432 2.408 12.456 ;
     RECT  0.06 12.456 2.408 12.528 ;
     RECT  0.084 12.528 2.408 12.552 ;
     RECT  0.06 12.552 2.408 12.624 ;
     RECT  0.084 12.624 2.408 12.648 ;
     RECT  0.06 12.648 2.408 12.72 ;
     RECT  0.084 12.72 2.408 12.744 ;
     RECT  0.06 12.744 2.408 12.816 ;
     RECT  0.084 12.816 2.408 12.84 ;
     RECT  0.06 12.84 2.408 12.912 ;
     RECT  0.084 12.912 2.408 12.936 ;
     RECT  0.06 12.936 2.408 13.008 ;
     RECT  0.084 13.008 2.408 13.032 ;
     RECT  0.06 13.032 2.408 13.104 ;
     RECT  0.084 13.104 2.408 13.128 ;
     RECT  0.06 13.128 2.408 13.2 ;
     RECT  0.084 13.2 2.408 13.224 ;
     RECT  0.06 13.224 2.408 13.296 ;
     RECT  0.084 13.296 2.408 13.32 ;
     RECT  0.06 13.32 2.408 13.392 ;
     RECT  0.084 13.392 2.408 13.416 ;
     RECT  0.06 13.416 2.408 13.488 ;
     RECT  0.084 13.488 2.408 13.512 ;
     RECT  0.06 13.512 2.408 13.584 ;
     RECT  0.084 13.584 2.408 13.608 ;
     RECT  0.06 13.608 2.408 13.68 ;
     RECT  0.084 13.68 2.408 13.704 ;
     RECT  0.06 13.704 2.408 13.776 ;
     RECT  0.084 13.776 2.408 13.8 ;
     RECT  0.06 13.8 2.408 13.872 ;
     RECT  0.084 13.872 2.408 13.896 ;
     RECT  0.06 13.896 2.408 13.968 ;
     RECT  0.084 13.968 2.408 13.992 ;
     RECT  0.06 13.992 2.408 14.064 ;
     RECT  0.084 14.064 2.408 14.088 ;
     RECT  0.06 14.088 2.408 14.16 ;
     RECT  0.084 14.16 2.408 14.184 ;
     RECT  0.06 14.184 2.408 14.256 ;
     RECT  0.084 14.256 2.408 14.28 ;
     RECT  0.06 14.28 2.408 14.352 ;
     RECT  0.084 14.352 2.408 14.376 ;
     RECT  0.06 14.376 2.408 14.448 ;
     RECT  0.084 14.448 2.408 14.472 ;
     RECT  0.06 14.472 2.408 14.544 ;
     RECT  0.084 14.544 2.408 14.568 ;
     RECT  0.06 14.568 2.408 14.64 ;
     RECT  0.084 14.64 2.408 14.664 ;
     RECT  0.06 14.664 2.408 14.736 ;
     RECT  0.084 14.736 2.408 14.76 ;
     RECT  0.06 14.76 2.408 14.832 ;
     RECT  0.084 14.832 2.408 14.856 ;
     RECT  0.06 14.856 2.408 14.928 ;
     RECT  0.084 14.928 2.408 14.952 ;
     RECT  0.06 14.952 2.408 15.024 ;
     RECT  0.084 15.024 2.408 15.048 ;
     RECT  0.06 15.048 2.408 15.12 ;
     RECT  0.084 15.12 2.408 15.144 ;
     RECT  0.06 15.144 2.408 15.216 ;
     RECT  0.084 15.216 2.408 15.24 ;
     RECT  0.06 15.24 2.408 15.312 ;
     RECT  0.084 15.312 2.408 15.336 ;
     RECT  0.06 15.336 2.408 15.408 ;
     RECT  0.084 15.408 2.408 15.432 ;
     RECT  0.06 15.432 2.408 15.504 ;
     RECT  0.084 15.504 2.408 15.528 ;
     RECT  0.06 15.528 2.408 15.6 ;
     RECT  0.084 15.6 2.408 15.624 ;
     RECT  0.06 15.624 2.408 15.696 ;
     RECT  0.084 15.696 2.408 15.72 ;
     RECT  0.06 15.72 2.408 15.792 ;
     RECT  0.084 15.792 2.408 15.816 ;
     RECT  0.06 15.816 2.408 15.888 ;
     RECT  0.084 15.888 2.408 15.912 ;
     RECT  0.06 15.912 2.408 15.984 ;
     RECT  0.084 15.984 2.408 16.008 ;
     RECT  0.06 16.008 2.408 16.08 ;
     RECT  0.084 16.08 2.408 16.104 ;
     RECT  0.06 16.104 2.408 16.176 ;
     RECT  0.084 16.176 2.408 16.2 ;
     RECT  0.06 16.2 2.408 16.272 ;
     RECT  0.084 16.272 2.408 16.296 ;
     RECT  0.06 16.296 2.408 16.368 ;
     RECT  0.084 16.368 2.408 16.392 ;
     RECT  0.06 16.392 2.408 16.464 ;
     RECT  0.084 16.464 2.408 16.488 ;
     RECT  0.06 16.488 2.408 16.56 ;
     RECT  0.084 16.56 2.408 16.584 ;
     RECT  0.06 16.584 2.408 16.656 ;
     RECT  0.084 16.656 2.408 16.68 ;
     RECT  0.06 16.68 2.408 16.752 ;
     RECT  0.084 16.752 2.408 16.776 ;
     RECT  0.06 16.776 2.408 16.848 ;
     RECT  0.084 16.848 2.408 16.872 ;
     RECT  0.06 16.872 2.408 16.944 ;
     RECT  0.084 16.944 2.408 16.968 ;
     RECT  0.06 16.968 2.408 17.04 ;
     RECT  0.084 17.04 2.408 17.064 ;
     RECT  0.06 17.064 2.408 17.136 ;
     RECT  0.084 17.136 2.408 17.16 ;
     RECT  0.06 17.16 2.408 17.232 ;
     RECT  0.084 17.232 2.408 17.256 ;
     RECT  0.06 17.256 2.408 17.328 ;
     RECT  0.084 17.328 2.408 17.352 ;
     RECT  0.06 17.352 2.408 17.424 ;
     RECT  0.084 17.424 2.408 17.448 ;
     RECT  0.06 17.448 2.408 17.52 ;
     RECT  0.084 17.52 2.408 17.544 ;
     RECT  0.06 17.544 2.408 17.616 ;
     RECT  0.084 17.616 2.408 17.64 ;
     RECT  0.06 17.64 2.408 17.712 ;
     RECT  0.084 17.712 2.408 17.736 ;
     RECT  0.06 17.736 2.408 17.808 ;
     RECT  0.084 17.808 2.408 17.832 ;
     RECT  0.06 17.832 2.408 17.904 ;
     RECT  0.084 17.904 2.408 17.928 ;
     RECT  0.06 17.928 2.408 18 ;
     RECT  0.084 18 2.408 18.024 ;
     RECT  0.06 18.024 2.408 18.096 ;
     RECT  0.084 18.096 2.408 18.12 ;
     RECT  0.06 18.12 2.408 18.192 ;
     RECT  0.084 18.192 2.408 18.216 ;
     RECT  0.06 18.216 2.408 18.288 ;
     RECT  0.084 18.288 2.408 18.312 ;
     RECT  0.06 18.312 2.408 18.384 ;
     RECT  0.084 18.384 2.408 18.408 ;
     RECT  0.06 18.408 2.408 18.48 ;
     RECT  0.084 18.48 2.408 18.504 ;
     RECT  0.06 18.504 2.408 18.576 ;
     RECT  0.084 18.576 2.408 18.6 ;
     RECT  0.06 18.6 2.408 18.672 ;
     RECT  0.084 18.672 2.408 18.696 ;
     RECT  0.06 18.696 2.408 18.768 ;
     RECT  0.084 18.768 2.408 18.792 ;
     RECT  0.06 18.792 2.408 18.864 ;
     RECT  0.084 18.864 2.408 18.888 ;
     RECT  0.06 18.888 2.408 18.96 ;
     RECT  0.084 18.96 2.408 18.984 ;
     RECT  0.06 18.984 2.408 19.056 ;
     RECT  0.084 19.056 2.408 19.08 ;
     RECT  0.06 19.08 2.408 19.152 ;
     RECT  0.084 19.152 2.408 19.176 ;
     RECT  0.06 19.176 2.408 19.248 ;
     RECT  0.084 19.248 2.408 19.272 ;
     RECT  0.06 19.272 2.408 19.344 ;
     RECT  0.084 19.344 2.408 19.368 ;
     RECT  0.06 19.368 2.408 19.44 ;
     RECT  0.084 19.44 2.408 19.464 ;
     RECT  0.06 19.464 2.408 19.536 ;
     RECT  0.084 19.536 2.408 19.56 ;
     RECT  0.06 19.56 2.408 19.632 ;
     RECT  0.084 19.632 2.408 19.656 ;
     RECT  0.06 19.656 2.408 19.728 ;
     RECT  0.084 19.728 2.408 19.752 ;
     RECT  0.06 19.752 2.408 19.824 ;
     RECT  0.084 19.824 2.408 19.848 ;
     RECT  0.06 19.848 2.408 19.92 ;
     RECT  0.084 19.92 2.408 19.944 ;
     RECT  0.06 19.944 2.408 20.016 ;
     RECT  0.084 20.016 2.408 20.04 ;
     RECT  0.06 20.04 2.408 20.112 ;
     RECT  0.084 20.112 2.408 20.136 ;
     RECT  0.06 20.136 2.408 20.208 ;
     RECT  0.084 20.208 2.408 20.232 ;
     RECT  0.06 20.232 2.408 20.304 ;
     RECT  0.084 20.304 2.408 20.328 ;
     RECT  0.06 20.328 2.408 20.4 ;
     RECT  0.084 20.4 2.408 20.424 ;
     RECT  0.06 20.424 2.408 20.496 ;
     RECT  0.084 20.496 2.408 20.52 ;
     RECT  0.06 20.52 2.408 20.592 ;
     RECT  0.084 20.592 2.408 20.616 ;
     RECT  0.06 20.616 2.408 20.688 ;
     RECT  0.084 20.688 2.408 20.712 ;
     RECT  0.06 20.712 2.408 20.784 ;
     RECT  0.084 20.784 2.408 20.808 ;
     RECT  0.06 20.808 2.408 20.88 ;
     RECT  0.084 20.88 2.408 20.904 ;
     RECT  0.06 20.904 2.408 20.976 ;
     RECT  0.084 20.976 2.408 21 ;
     RECT  0.06 21 2.408 21.072 ;
     RECT  0.084 21.072 2.408 21.096 ;
     RECT  0.06 21.096 2.408 21.168 ;
     RECT  0.084 21.168 2.408 21.192 ;
     RECT  0.06 21.192 2.408 21.264 ;
     RECT  0.084 21.264 2.408 21.288 ;
     RECT  0.06 21.288 2.408 21.36 ;
     RECT  0.084 21.36 2.408 21.384 ;
     RECT  0.06 21.384 2.408 21.456 ;
     RECT  0.084 21.456 2.408 21.48 ;
     RECT  0.06 21.48 2.408 21.552 ;
     RECT  0.084 21.552 2.408 21.576 ;
     RECT  0.06 21.576 2.408 21.648 ;
     RECT  0.084 21.648 2.408 21.672 ;
     RECT  0.06 21.672 2.408 21.744 ;
     RECT  0.084 21.744 2.408 21.768 ;
     RECT  0.06 21.768 2.408 21.84 ;
     RECT  0.084 21.84 2.408 21.864 ;
     RECT  0.06 21.864 2.408 21.936 ;
     RECT  0.084 21.936 2.408 21.96 ;
     RECT  0.06 21.96 2.408 22.032 ;
     RECT  0.084 22.032 2.408 22.056 ;
     RECT  0.06 22.056 2.408 22.128 ;
     RECT  0.084 22.128 2.408 22.152 ;
     RECT  0.06 22.152 2.408 22.224 ;
     RECT  0.084 22.224 2.408 22.248 ;
     RECT  0.06 22.248 2.408 22.32 ;
     RECT  0.084 22.32 2.408 22.344 ;
     RECT  0.06 22.344 2.408 22.416 ;
     RECT  0.084 22.416 2.408 22.44 ;
     RECT  0.06 22.44 2.408 22.512 ;
     RECT  0.084 22.512 2.408 22.536 ;
     RECT  0.06 22.536 2.408 22.608 ;
     RECT  0.084 22.608 2.408 22.632 ;
     RECT  0.06 22.632 2.408 22.704 ;
     RECT  0.084 22.704 2.408 22.728 ;
     RECT  0.06 22.728 2.408 22.8 ;
     RECT  0.084 22.8 2.408 22.824 ;
     RECT  0.06 22.824 2.408 22.896 ;
     RECT  0.084 22.896 2.408 22.92 ;
     RECT  0.06 22.92 2.408 22.992 ;
     RECT  0.084 22.992 2.408 23.016 ;
     RECT  0.06 23.016 2.408 23.088 ;
     RECT  0.084 23.088 2.408 23.112 ;
     RECT  0.06 23.112 2.408 23.184 ;
     RECT  0.084 23.184 2.408 23.208 ;
     RECT  0.06 23.208 2.408 23.28 ;
     RECT  0.084 23.28 2.408 23.304 ;
     RECT  2.408 2.148 2.512 27.552 ;
     RECT  2.512 2.418 2.6 27.552 ;
     RECT  2.6 2.418 2.704 27.822 ;
     RECT  2.704 10.992 2.765 23.304 ;
     RECT  2.765 11.184 5.108 23.304 ;
     RECT  5.108 2.148 5.212 27.552 ;
     RECT  5.212 2.418 5.3 27.552 ;
     RECT  5.3 2.418 5.404 27.822 ;
     RECT  5.404 11.184 7.808 23.304 ;
     RECT  7.808 2.148 7.912 27.552 ;
     RECT  7.912 2.418 8 27.552 ;
     RECT  8 2.418 8.104 27.822 ;
     RECT  8.104 11.184 10.508 23.304 ;
     RECT  10.508 2.148 10.612 27.552 ;
     RECT  10.612 2.418 10.7 27.552 ;
     RECT  10.7 2.418 10.804 27.822 ;
     RECT  10.804 11.184 13.208 23.304 ;
     RECT  13.208 2.148 13.312 27.552 ;
     RECT  13.312 2.418 13.4 27.552 ;
     RECT  13.4 2.418 13.504 27.822 ;
     RECT  13.504 11.184 15.908 23.304 ;
     RECT  15.908 2.148 16.012 27.552 ;
     RECT  16.012 2.418 16.1 27.552 ;
     RECT  16.1 2.418 16.204 27.822 ;
     RECT  16.204 11.184 18.608 23.304 ;
     RECT  18.608 2.148 18.712 27.552 ;
     RECT  18.712 2.418 18.8 27.552 ;
     RECT  18.8 2.418 18.904 27.822 ;
     RECT  18.904 11.184 21.308 23.304 ;
     RECT  21.308 2.148 21.412 27.552 ;
     RECT  21.412 2.418 21.5 27.552 ;
     RECT  21.5 2.418 21.604 27.822 ;
     RECT  21.604 11.184 24.008 23.304 ;
     RECT  24.008 2.148 24.112 27.552 ;
     RECT  24.112 2.418 24.2 27.552 ;
     RECT  24.2 2.418 24.304 27.822 ;
     RECT  24.304 11.184 26.708 23.304 ;
     RECT  26.549 26.784 26.708 26.808 ;
     RECT  26.708 2.148 26.812 27.552 ;
     RECT  26.812 2.418 26.9 27.552 ;
     RECT  26.9 2.418 27.004 27.822 ;
     RECT  27.004 25.536 27.061 27.822 ;
     RECT  27.061 25.536 27.203 27.912 ;
     RECT  27.157 30.096 27.241 30.12 ;
     RECT  27.203 25.536 27.299 27.72 ;
     RECT  27.241 29.664 27.325 30.12 ;
     RECT  27.325 30.096 27.353 30.12 ;
     RECT  27.299 25.536 27.827 27.624 ;
     RECT  27.827 25.728 27.965 27.624 ;
     RECT  27.965 26.304 28.397 26.328 ;
     RECT  27.965 27.6 28.397 27.624 ;
     RECT  27.004 11.184 29.408 23.304 ;
     RECT  29.408 2.148 29.512 27.552 ;
     RECT  29.512 2.418 29.6 27.552 ;
     RECT  29.6 2.418 29.704 27.822 ;
     RECT  29.704 15.312 30.593 15.528 ;
     RECT  29.704 16.56 30.593 19.896 ;
     RECT  30.593 16.56 30.701 19.608 ;
     RECT  29.704 11.184 30.769 14.184 ;
     RECT  30.593 15.504 30.845 15.528 ;
     RECT  30.769 11.136 31.705 14.184 ;
     RECT  31.705 11.136 32.108 14.808 ;
     RECT  30.701 16.56 32.108 19.272 ;
     RECT  29.704 20.976 32.108 22.056 ;
     RECT  29.704 23.088 32.108 23.112 ;
     RECT  32.108 2.148 32.212 27.552 ;
     RECT  32.212 2.418 32.3 27.552 ;
     RECT  32.3 2.418 32.404 27.822 ;
     RECT  32.404 11.136 33.329 14.184 ;
     RECT  33.329 11.664 34.808 14.184 ;
     RECT  32.404 17.616 34.808 18.216 ;
     RECT  32.404 19.248 34.808 19.272 ;
     RECT  34.808 2.148 34.912 27.552 ;
     RECT  34.912 2.418 35 27.552 ;
     RECT  35 2.418 35.104 27.822 ;
     RECT  35.104 11.664 37.508 12.888 ;
     RECT  35.104 13.872 37.508 14.184 ;
     RECT  35.104 17.616 37.508 18.216 ;
     RECT  35.104 19.248 37.508 19.272 ;
     RECT  37.508 2.148 37.612 27.552 ;
     RECT  37.612 2.418 37.7 27.552 ;
     RECT  37.7 2.418 37.804 27.822 ;
     RECT  37.804 11.664 40.208 12.888 ;
     RECT  37.804 13.872 40.208 14.184 ;
     RECT  37.804 17.616 40.208 18.216 ;
     RECT  37.804 19.248 40.208 19.272 ;
     RECT  40.208 2.148 40.312 27.552 ;
     RECT  40.312 2.418 40.4 27.552 ;
     RECT  40.4 2.418 40.504 27.822 ;
     RECT  40.504 11.664 42.908 12.888 ;
     RECT  40.504 13.872 42.908 14.184 ;
     RECT  40.504 17.616 42.908 18.216 ;
     RECT  40.504 19.248 42.908 19.272 ;
     RECT  42.908 2.148 43.012 27.552 ;
     RECT  43.012 2.418 43.1 27.552 ;
     RECT  43.1 2.418 43.204 27.822 ;
     RECT  43.204 17.616 44.821 18.216 ;
     RECT  43.204 11.664 45.608 14.184 ;
     RECT  44.821 16.8 45.608 18.216 ;
     RECT  43.204 19.248 45.608 19.272 ;
     RECT  45.277 21.696 45.608 21.72 ;
     RECT  45.608 2.148 45.712 27.552 ;
     RECT  45.712 2.418 45.8 27.552 ;
     RECT  45.8 2.418 45.904 27.822 ;
     RECT  45.904 18.192 46.307 18.216 ;
     RECT  45.904 21.696 46.333 21.816 ;
     RECT  46.333 21.696 46.451 21.72 ;
     RECT  45.904 11.664 46.477 14.232 ;
     RECT  45.904 19.248 47.221 19.272 ;
     RECT  47.221 18.816 47.297 19.272 ;
     RECT  47.297 18.816 47.305 18.984 ;
     RECT  46.477 11.664 48.308 14.184 ;
     RECT  45.904 16.032 48.308 16.824 ;
     RECT  47.305 18.96 48.308 18.984 ;
     RECT  48.308 2.148 48.412 27.552 ;
     RECT  48.412 2.418 48.5 27.552 ;
     RECT  48.5 2.418 48.604 27.822 ;
     RECT  48.604 16.032 50.713 16.824 ;
     RECT  48.604 11.664 51.008 14.184 ;
     RECT  50.713 16.032 51.008 16.92 ;
     RECT  48.604 18.96 51.008 18.984 ;
     RECT  51.008 2.148 51.112 27.552 ;
     RECT  51.112 2.418 51.2 27.552 ;
     RECT  51.2 2.418 51.304 27.822 ;
     RECT  51.304 11.664 53.708 14.184 ;
     RECT  51.304 16.032 53.708 16.92 ;
     RECT  51.304 18.96 53.708 18.984 ;
     RECT  53.708 2.148 53.812 27.552 ;
     RECT  53.812 2.418 53.9 27.552 ;
     RECT  53.9 2.418 54.004 27.822 ;
     RECT  54.004 11.664 54.065 14.184 ;
     RECT  54.004 18.96 55.177 18.984 ;
     RECT  54.004 16.032 55.181 16.92 ;
     RECT  55.285 10.656 55.357 10.68 ;
     RECT  54.065 11.712 55.357 14.184 ;
     RECT  55.181 16.032 55.357 16.776 ;
     RECT  55.177 18.192 55.361 18.984 ;
     RECT  55.357 10.656 55.573 14.184 ;
     RECT  55.249 8.496 56.197 8.52 ;
     RECT  56.197 7.92 56.408 8.52 ;
     RECT  55.573 9.744 56.408 14.184 ;
     RECT  55.357 15.456 56.408 16.776 ;
     RECT  55.361 18.96 56.408 18.984 ;
     RECT  56.408 2.148 56.512 27.552 ;
     RECT  56.512 2.418 56.6 27.552 ;
     RECT  56.6 2.418 56.704 27.822 ;
     RECT  56.704 7.536 57.233 18.696 ;
     RECT  57.233 7.536 57.685 18.552 ;
     RECT  57.685 6.816 57.773 18.552 ;
     RECT  57.773 7.584 57.917 18.552 ;
     RECT  57.917 7.632 59.108 18.552 ;
     RECT  59.108 2.148 59.212 27.552 ;
     RECT  59.212 2.418 59.3 27.552 ;
     RECT  59.3 2.418 59.404 27.822 ;
     RECT  59.404 7.008 60.221 18.552 ;
     RECT  60.221 7.008 60.227 18.408 ;
     RECT  60.227 7.008 60.419 17.208 ;
     RECT  60.227 18.384 60.581 18.408 ;
     RECT  60.419 10.32 60.617 17.208 ;
     RECT  60.419 7.008 60.653 9.24 ;
     RECT  60.617 16.896 61.405 17.208 ;
     RECT  60.653 7.008 61.808 8.472 ;
     RECT  60.617 10.32 61.808 15.72 ;
     RECT  61.405 16.896 61.808 18.024 ;
     RECT  61.808 2.148 61.912 27.552 ;
     RECT  61.912 2.418 62 27.552 ;
     RECT  62 2.418 62.104 27.822 ;
     RECT  62.104 6.864 64.692 6.888 ;
     RECT  62.104 6.888 64.716 6.96 ;
     RECT  62.104 6.96 64.692 6.984 ;
     RECT  62.104 6.984 64.716 7.056 ;
     RECT  62.104 7.056 64.692 7.08 ;
     RECT  62.104 7.08 64.716 7.152 ;
     RECT  62.104 7.152 64.692 7.176 ;
     RECT  62.104 7.176 64.716 7.248 ;
     RECT  62.104 7.248 64.692 7.272 ;
     RECT  62.104 7.272 64.716 7.344 ;
     RECT  62.104 7.344 64.692 7.368 ;
     RECT  62.104 7.368 64.716 7.44 ;
     RECT  62.104 7.44 64.692 7.464 ;
     RECT  62.104 7.464 64.716 7.536 ;
     RECT  62.104 7.536 64.692 7.56 ;
     RECT  62.104 7.56 64.716 7.632 ;
     RECT  62.104 7.632 64.692 7.656 ;
     RECT  62.104 7.656 64.716 7.728 ;
     RECT  62.104 7.728 64.692 7.752 ;
     RECT  62.104 7.752 64.716 7.824 ;
     RECT  62.104 7.824 64.692 7.848 ;
     RECT  62.104 7.848 64.716 7.92 ;
     RECT  62.104 7.92 64.692 7.944 ;
     RECT  62.104 7.944 64.716 8.016 ;
     RECT  62.104 8.016 64.692 8.04 ;
     RECT  62.104 8.04 64.716 8.112 ;
     RECT  62.104 8.112 64.692 8.136 ;
     RECT  62.104 8.136 64.716 8.208 ;
     RECT  62.104 8.208 64.692 8.232 ;
     RECT  62.104 8.232 64.716 8.304 ;
     RECT  62.104 8.304 64.692 8.328 ;
     RECT  62.104 8.328 64.716 8.4 ;
     RECT  62.104 8.4 64.692 8.424 ;
     RECT  62.104 8.424 64.716 8.496 ;
     RECT  62.104 8.496 64.692 8.52 ;
     RECT  62.104 8.52 64.716 8.592 ;
     RECT  62.104 8.592 64.692 8.616 ;
     RECT  62.104 8.616 64.716 8.688 ;
     RECT  62.104 8.688 64.692 8.712 ;
     RECT  62.104 8.712 64.716 8.784 ;
     RECT  62.104 8.784 64.692 8.808 ;
     RECT  62.104 8.808 64.716 8.88 ;
     RECT  62.104 8.88 64.692 8.904 ;
     RECT  62.104 8.904 64.716 8.976 ;
     RECT  62.104 8.976 64.692 9 ;
     RECT  62.104 9 64.716 9.072 ;
     RECT  62.104 9.072 64.692 9.096 ;
     RECT  62.104 9.096 64.716 9.168 ;
     RECT  62.104 9.168 64.692 9.192 ;
     RECT  62.104 9.192 64.716 9.264 ;
     RECT  62.104 9.264 64.692 9.288 ;
     RECT  62.104 9.288 64.716 9.36 ;
     RECT  62.104 9.36 64.692 9.384 ;
     RECT  62.104 9.384 64.716 9.456 ;
     RECT  62.104 9.456 64.692 9.48 ;
     RECT  62.104 9.48 64.716 9.552 ;
     RECT  62.104 9.552 64.692 9.576 ;
     RECT  62.104 9.576 64.716 9.648 ;
     RECT  62.104 9.648 64.692 9.672 ;
     RECT  62.104 9.672 64.716 9.744 ;
     RECT  62.104 9.744 64.692 9.768 ;
     RECT  62.104 9.768 64.716 9.84 ;
     RECT  62.104 9.84 64.692 9.864 ;
     RECT  62.104 9.864 64.716 9.936 ;
     RECT  62.104 9.936 64.692 9.96 ;
     RECT  62.104 9.96 64.716 10.032 ;
     RECT  62.104 10.032 64.692 10.056 ;
     RECT  62.104 10.056 64.716 10.128 ;
     RECT  62.104 10.128 64.692 10.152 ;
     RECT  62.104 10.152 64.716 10.224 ;
     RECT  62.104 10.224 64.692 10.248 ;
     RECT  62.104 10.248 64.716 10.32 ;
     RECT  62.104 10.32 64.692 10.344 ;
     RECT  62.104 10.344 64.716 10.416 ;
     RECT  62.104 10.416 64.692 10.44 ;
     RECT  62.104 10.44 64.716 10.512 ;
     RECT  62.104 10.512 64.692 10.536 ;
     RECT  62.104 10.536 64.716 10.608 ;
     RECT  62.104 10.608 64.692 10.632 ;
     RECT  62.104 10.632 64.716 10.704 ;
     RECT  62.104 10.704 64.692 10.728 ;
     RECT  62.104 10.728 64.716 10.8 ;
     RECT  62.104 10.8 64.692 10.824 ;
     RECT  62.104 10.824 64.716 10.896 ;
     RECT  62.104 10.896 64.692 10.92 ;
     RECT  62.104 10.92 64.716 10.992 ;
     RECT  62.104 10.992 64.692 11.016 ;
     RECT  62.104 11.016 64.716 11.088 ;
     RECT  62.104 11.088 64.692 11.112 ;
     RECT  62.104 11.112 64.716 11.184 ;
     RECT  62.104 11.184 64.692 11.208 ;
     RECT  62.104 11.208 64.716 11.28 ;
     RECT  62.104 11.28 64.692 11.304 ;
     RECT  62.104 11.304 64.716 11.376 ;
     RECT  62.104 11.376 64.692 11.4 ;
     RECT  62.104 11.4 64.716 11.472 ;
     RECT  62.104 11.472 64.692 11.496 ;
     RECT  62.104 11.496 64.716 11.568 ;
     RECT  62.104 11.568 64.692 11.592 ;
     RECT  62.104 11.592 64.716 11.664 ;
     RECT  62.104 11.664 64.692 11.688 ;
     RECT  62.104 11.688 64.716 11.76 ;
     RECT  62.104 11.76 64.692 11.784 ;
     RECT  62.104 11.784 64.716 11.856 ;
     RECT  62.104 11.856 64.692 11.88 ;
     RECT  62.104 11.88 64.716 11.952 ;
     RECT  62.104 11.952 64.692 11.976 ;
     RECT  62.104 11.976 64.716 12.048 ;
     RECT  62.104 12.048 64.692 12.072 ;
     RECT  62.104 12.072 64.716 12.144 ;
     RECT  62.104 12.144 64.692 12.168 ;
     RECT  62.104 12.168 64.716 12.24 ;
     RECT  62.104 12.24 64.692 12.264 ;
     RECT  62.104 12.264 64.716 12.336 ;
     RECT  62.104 12.336 64.692 12.36 ;
     RECT  62.104 12.36 64.716 12.432 ;
     RECT  62.104 12.432 64.692 12.456 ;
     RECT  62.104 12.456 64.716 12.528 ;
     RECT  62.104 12.528 64.692 12.552 ;
     RECT  62.104 12.552 64.716 12.624 ;
     RECT  62.104 12.624 64.692 12.648 ;
     RECT  62.104 12.648 64.716 12.72 ;
     RECT  62.104 12.72 64.692 12.744 ;
     RECT  62.104 12.744 64.716 12.816 ;
     RECT  62.104 12.816 64.692 12.84 ;
     RECT  62.104 12.84 64.716 12.912 ;
     RECT  62.104 12.912 64.692 12.936 ;
     RECT  62.104 12.936 64.716 13.008 ;
     RECT  62.104 13.008 64.692 13.032 ;
     RECT  62.104 13.032 64.716 13.104 ;
     RECT  62.104 13.104 64.692 13.128 ;
     RECT  62.104 13.128 64.716 13.2 ;
     RECT  62.104 13.2 64.692 13.224 ;
     RECT  62.104 13.224 64.716 13.296 ;
     RECT  62.104 13.296 64.692 13.32 ;
     RECT  62.104 13.32 64.716 13.392 ;
     RECT  62.104 13.392 64.692 13.416 ;
     RECT  62.104 13.416 64.716 13.488 ;
     RECT  62.104 13.488 64.692 13.512 ;
     RECT  62.104 13.512 64.716 13.584 ;
     RECT  62.104 13.584 64.692 13.608 ;
     RECT  62.104 13.608 64.716 13.68 ;
     RECT  62.104 13.68 64.692 13.704 ;
     RECT  62.104 13.704 64.716 13.776 ;
     RECT  62.104 13.776 64.692 13.8 ;
     RECT  62.104 13.8 64.716 13.872 ;
     RECT  62.104 13.872 64.692 13.896 ;
     RECT  62.104 13.896 64.716 13.968 ;
     RECT  62.104 13.968 64.692 13.992 ;
     RECT  62.104 13.992 64.716 14.064 ;
     RECT  62.104 14.064 64.692 14.088 ;
     RECT  62.104 14.088 64.716 14.16 ;
     RECT  62.104 14.16 64.692 14.184 ;
     RECT  62.104 14.184 64.716 14.256 ;
     RECT  62.104 14.256 64.692 14.28 ;
     RECT  62.104 14.28 64.716 14.352 ;
     RECT  62.104 14.352 64.692 14.376 ;
     RECT  62.104 14.376 64.716 14.448 ;
     RECT  62.104 14.448 64.692 14.472 ;
     RECT  62.104 14.472 64.716 14.544 ;
     RECT  62.104 14.544 64.692 14.568 ;
     RECT  62.104 14.568 64.716 14.64 ;
     RECT  62.104 14.64 64.692 14.664 ;
     RECT  62.104 14.664 64.716 14.736 ;
     RECT  62.104 14.736 64.692 14.76 ;
     RECT  62.104 14.76 64.716 14.832 ;
     RECT  62.104 14.832 64.692 14.856 ;
     RECT  62.104 14.856 64.716 14.928 ;
     RECT  62.104 14.928 64.692 14.952 ;
     RECT  62.104 14.952 64.716 15.024 ;
     RECT  62.104 15.024 64.692 15.048 ;
     RECT  62.104 15.048 64.716 15.12 ;
     RECT  62.104 15.12 64.692 15.144 ;
     RECT  62.104 15.144 64.716 15.216 ;
     RECT  62.104 15.216 64.692 15.24 ;
     RECT  62.104 15.24 64.716 15.312 ;
     RECT  62.104 15.312 64.692 15.336 ;
     RECT  62.104 15.336 64.716 15.408 ;
     RECT  62.104 15.408 64.692 15.432 ;
     RECT  62.104 15.432 64.716 15.504 ;
     RECT  62.104 15.504 64.692 15.528 ;
     RECT  62.104 15.528 64.716 15.6 ;
     RECT  62.104 15.6 64.692 15.624 ;
     RECT  62.104 15.624 64.716 15.696 ;
     RECT  62.104 15.696 64.692 15.72 ;
     RECT  62.104 15.72 64.716 15.792 ;
     RECT  62.104 15.792 64.692 15.816 ;
     RECT  62.104 15.816 64.716 15.888 ;
     RECT  62.104 15.888 64.692 15.912 ;
     RECT  62.104 15.912 64.716 15.984 ;
     RECT  62.104 15.984 64.692 16.008 ;
     RECT  62.104 16.008 64.716 16.08 ;
     RECT  62.104 16.08 64.692 16.104 ;
     RECT  62.104 16.104 64.716 16.176 ;
     RECT  62.104 16.176 64.692 16.2 ;
     RECT  62.104 16.2 64.716 16.272 ;
     RECT  62.104 16.272 64.692 16.296 ;
     RECT  62.104 16.296 64.716 16.368 ;
     RECT  62.104 16.368 64.692 16.392 ;
     RECT  62.104 16.392 64.716 16.464 ;
     RECT  62.104 16.464 64.692 16.488 ;
     RECT  62.104 16.488 64.716 16.56 ;
     RECT  62.104 16.56 64.692 16.584 ;
     RECT  62.104 16.584 64.716 16.656 ;
     RECT  62.104 16.656 64.692 16.68 ;
     RECT  62.104 16.68 64.716 16.752 ;
     RECT  62.104 16.752 64.692 16.776 ;
     RECT  62.104 16.776 64.716 16.848 ;
     RECT  62.104 16.848 64.692 16.872 ;
     RECT  62.104 16.872 64.716 16.944 ;
     RECT  62.104 16.944 64.692 16.968 ;
     RECT  62.104 16.968 64.716 17.04 ;
     RECT  62.104 17.04 64.692 17.064 ;
     RECT  62.104 17.064 64.716 17.136 ;
     RECT  62.104 17.136 64.692 17.16 ;
     RECT  62.104 17.16 64.716 17.232 ;
     RECT  62.104 17.232 64.692 17.256 ;
     RECT  62.104 17.256 64.716 17.328 ;
     RECT  62.104 17.328 64.692 17.352 ;
     RECT  62.104 17.352 64.716 17.424 ;
     RECT  62.104 17.424 64.692 17.448 ;
     RECT  62.104 17.448 64.716 17.52 ;
     RECT  62.104 17.52 64.692 17.544 ;
     RECT  62.104 17.544 64.716 17.616 ;
     RECT  62.104 17.616 64.692 17.64 ;
     RECT  62.104 17.64 64.716 17.712 ;
     RECT  62.104 17.712 64.692 17.736 ;
     RECT  62.104 17.736 64.716 17.808 ;
     RECT  62.104 17.808 64.692 17.832 ;
     RECT  62.104 17.832 64.716 17.904 ;
     RECT  62.104 17.904 64.692 17.928 ;
     RECT  62.104 17.928 64.716 18 ;
     RECT  62.104 18 64.692 18.024 ;
     RECT  62.104 18.024 64.716 18.096 ;
     RECT  62.104 18.096 64.692 18.12 ;
     RECT  62.104 18.12 64.716 18.192 ;
     RECT  62.104 18.192 64.692 18.216 ;
     RECT  62.104 18.216 64.716 18.288 ;
     RECT  62.104 18.288 64.692 18.312 ;
     RECT  62.104 18.312 64.716 18.384 ;
     RECT  62.104 18.384 64.692 18.408 ;
     RECT  62.104 18.408 64.716 18.48 ;
     RECT  62.104 18.48 64.692 18.504 ;
     RECT  62.104 18.504 64.716 18.576 ;
     RECT  62.104 18.576 64.692 18.6 ;
     RECT  62.104 18.6 64.716 18.672 ;
     RECT  62.104 18.672 64.692 18.696 ;
     RECT  62.104 18.696 64.716 18.768 ;
     RECT  62.104 18.768 64.692 18.792 ;
     RECT  62.104 18.792 64.716 18.864 ;
     RECT  62.104 18.864 64.692 18.888 ;
     RECT  62.104 18.888 64.716 18.96 ;
     RECT  62.104 18.96 64.692 18.984 ;
     RECT  62.104 18.984 64.716 19.056 ;
     RECT  62.104 19.056 64.692 19.08 ;
     RECT  64.716 7.872 64.757 7.896 ;
    LAYER M5 ;
     RECT  2.4 2.137 2.52 2.151 ;
     RECT  5.1 2.137 5.22 2.151 ;
     RECT  7.8 2.137 7.92 2.151 ;
     RECT  10.5 2.137 10.62 2.151 ;
     RECT  13.2 2.137 13.32 2.151 ;
     RECT  15.9 2.137 16.02 2.151 ;
     RECT  18.6 2.137 18.72 2.151 ;
     RECT  21.3 2.137 21.42 2.151 ;
     RECT  24 2.137 24.12 2.151 ;
     RECT  26.7 2.137 26.82 2.151 ;
     RECT  29.4 2.137 29.52 2.151 ;
     RECT  32.1 2.137 32.22 2.151 ;
     RECT  34.8 2.137 34.92 2.151 ;
     RECT  37.5 2.137 37.62 2.151 ;
     RECT  40.2 2.137 40.32 2.151 ;
     RECT  42.9 2.137 43.02 2.151 ;
     RECT  45.6 2.137 45.72 2.151 ;
     RECT  48.3 2.137 48.42 2.151 ;
     RECT  51 2.137 51.12 2.151 ;
     RECT  53.7 2.137 53.82 2.151 ;
     RECT  56.4 2.137 56.52 2.151 ;
     RECT  59.1 2.137 59.22 2.151 ;
     RECT  61.8 2.137 61.92 2.151 ;
     RECT  57.696 6.805 57.72 7.571 ;
     RECT  56.4 2.151 56.712 7.909 ;
     RECT  59.1 2.151 59.412 8.821 ;
     RECT  56.208 7.909 56.712 9.637 ;
     RECT  56.208 9.637 57.432 9.733 ;
     RECT  55.584 9.733 57.432 10.069 ;
     RECT  58.608 8.821 59.412 10.069 ;
     RECT  55.584 10.069 59.412 10.211 ;
     RECT  55.584 10.211 57.864 10.883 ;
     RECT  24 2.151 24.312 11.221 ;
     RECT  23.904 11.221 24.312 11.411 ;
     RECT  26.7 2.151 27.012 11.413 ;
     RECT  2.4 2.151 2.712 11.557 ;
     RECT  26.7 11.413 27.96 11.603 ;
     RECT  32.1 2.151 32.412 11.701 ;
     RECT  56.4 10.883 57.864 11.749 ;
     RECT  59.1 10.211 59.412 11.749 ;
     RECT  32.1 11.701 33.384 11.987 ;
     RECT  60.384 9.925 60.408 12.035 ;
     RECT  29.4 2.151 29.712 12.565 ;
     RECT  56.4 11.749 59.412 12.611 ;
     RECT  45.6 2.151 45.912 12.757 ;
     RECT  2.4 11.557 3.288 12.803 ;
     RECT  22.8 11.845 22.824 12.803 ;
     RECT  29.4 12.565 30.84 12.803 ;
     RECT  55.392 11.173 55.416 12.803 ;
     RECT  24 11.411 24.312 12.853 ;
     RECT  14.832 12.709 14.856 12.899 ;
     RECT  29.4 12.803 30.024 12.899 ;
     RECT  44.976 12.757 45.912 13.045 ;
     RECT  59.1 12.611 59.412 13.621 ;
     RECT  23.904 12.853 24.312 13.667 ;
     RECT  26.7 11.603 27.012 13.861 ;
     RECT  22.8 13.909 22.824 14.195 ;
     RECT  56.4 12.611 57.864 14.435 ;
     RECT  59.1 13.621 60.168 14.773 ;
     RECT  56.4 14.435 57.432 14.867 ;
     RECT  24 13.667 24.312 14.965 ;
     RECT  23.904 14.965 24.312 15.203 ;
     RECT  44.976 13.045 46.44 16.789 ;
     RECT  59.1 14.773 60.216 17.029 ;
     RECT  24 15.203 24.312 17.317 ;
     RECT  23.904 17.317 24.312 17.459 ;
     RECT  44.832 16.789 47.256 17.651 ;
     RECT  58.992 17.029 60.216 18.179 ;
     RECT  30.768 17.509 30.792 18.227 ;
     RECT  59.1 18.179 60.216 18.419 ;
     RECT  22.8 18.469 22.824 18.803 ;
     RECT  45.6 17.651 47.256 18.851 ;
     RECT  2.4 12.803 2.712 18.853 ;
     RECT  2.304 18.853 2.712 19.043 ;
     RECT  26.7 13.861 27.288 19.237 ;
     RECT  14.832 21.157 14.856 21.491 ;
     RECT  22.8 21.157 22.824 21.491 ;
     RECT  24 17.459 24.312 21.637 ;
     RECT  45.6 18.851 46.44 21.731 ;
     RECT  23.904 21.637 24.312 21.779 ;
     RECT  45.6 21.731 46.296 21.827 ;
     RECT  26.592 19.237 27.288 25.525 ;
     RECT  26.592 25.525 27.816 26.197 ;
     RECT  26.592 26.197 27.912 26.819 ;
     RECT  26.7 26.819 27.912 27.635 ;
     RECT  2.4 19.043 2.712 27.819 ;
     RECT  5.1 2.151 5.412 27.819 ;
     RECT  7.8 2.151 8.112 27.819 ;
     RECT  10.5 2.151 10.812 27.819 ;
     RECT  13.2 2.151 13.512 27.819 ;
     RECT  15.9 2.151 16.212 27.819 ;
     RECT  18.6 2.151 18.912 27.819 ;
     RECT  21.3 2.151 21.612 27.819 ;
     RECT  24 21.779 24.312 27.819 ;
     RECT  26.7 27.635 27.288 27.819 ;
     RECT  29.4 12.899 29.712 27.819 ;
     RECT  32.1 11.987 32.412 27.819 ;
     RECT  34.8 2.151 35.112 27.819 ;
     RECT  37.5 2.151 37.812 27.819 ;
     RECT  40.2 2.151 40.512 27.819 ;
     RECT  42.9 2.151 43.212 27.819 ;
     RECT  45.6 21.827 45.912 27.819 ;
     RECT  48.3 2.151 48.612 27.819 ;
     RECT  51 2.151 51.312 27.819 ;
     RECT  53.7 2.151 54.012 27.819 ;
     RECT  56.4 14.867 56.712 27.819 ;
     RECT  59.1 18.419 59.412 27.819 ;
     RECT  61.8 2.151 62.112 27.819 ;
     RECT  2.592 27.819 2.712 27.833 ;
     RECT  5.292 27.819 5.412 27.833 ;
     RECT  7.992 27.819 8.112 27.833 ;
     RECT  10.692 27.819 10.812 27.833 ;
     RECT  13.392 27.819 13.512 27.833 ;
     RECT  16.092 27.819 16.212 27.833 ;
     RECT  18.792 27.819 18.912 27.833 ;
     RECT  21.492 27.819 21.612 27.833 ;
     RECT  24.192 27.819 24.312 27.833 ;
     RECT  26.892 27.819 27.288 27.833 ;
     RECT  29.592 27.819 29.712 27.833 ;
     RECT  32.292 27.819 32.412 27.833 ;
     RECT  34.992 27.819 35.112 27.833 ;
     RECT  37.692 27.819 37.812 27.833 ;
     RECT  40.392 27.819 40.512 27.833 ;
     RECT  43.092 27.819 43.212 27.833 ;
     RECT  45.792 27.819 45.912 27.833 ;
     RECT  48.492 27.819 48.612 27.833 ;
     RECT  51.192 27.819 51.312 27.833 ;
     RECT  53.892 27.819 54.012 27.833 ;
     RECT  56.592 27.819 56.712 27.833 ;
     RECT  59.292 27.819 59.412 27.833 ;
     RECT  61.992 27.819 62.112 27.833 ;
     RECT  27.168 27.833 27.288 29.699 ;
     RECT  27.168 29.699 27.192 30.131 ;
     RECT  56.712 6.805 57.696 7.571 ;
     RECT  57.72 6.805 59.1 7.571 ;
     RECT  58.608 7.571 59.1 8.821 ;
     RECT  57.432 9.637 58.608 10.069 ;
     RECT  59.412 9.925 60.384 12.035 ;
     RECT  60.408 9.925 61.8 12.035 ;
     RECT  57.864 10.211 59.1 11.749 ;
     RECT  55.584 10.883 56.4 11.173 ;
     RECT  54.012 11.173 55.392 12.803 ;
     RECT  55.416 11.173 56.4 12.803 ;
     RECT  23.904 11.411 24 11.845 ;
     RECT  27.96 11.413 29.4 11.603 ;
     RECT  33.384 11.701 34.8 11.987 ;
     RECT  21.612 11.845 22.8 12.803 ;
     RECT  22.824 11.845 24 12.803 ;
     RECT  30.84 12.565 32.1 12.803 ;
     RECT  57.864 12.611 59.1 14.435 ;
     RECT  13.512 12.709 14.832 12.899 ;
     RECT  14.856 12.709 15.9 12.899 ;
     RECT  21.612 12.803 24 12.853 ;
     RECT  21.612 12.853 23.904 13.667 ;
     RECT  21.612 13.667 24 13.909 ;
     RECT  21.612 13.909 22.8 14.195 ;
     RECT  22.824 13.909 24 14.195 ;
     RECT  23.904 14.195 24 14.965 ;
     RECT  47.256 16.789 48.3 18.851 ;
     RECT  23.904 17.459 24 18.469 ;
     RECT  29.712 17.509 30.768 18.227 ;
     RECT  30.792 17.509 32.1 18.227 ;
     RECT  21.612 18.469 22.8 18.803 ;
     RECT  22.824 18.469 24 18.803 ;
     RECT  13.512 21.157 14.832 21.491 ;
     RECT  14.856 21.157 15.9 21.491 ;
     RECT  21.612 21.157 22.8 21.491 ;
     RECT  22.824 21.157 24 21.491 ;
     RECT  23.904 21.491 24 21.637 ;
     RECT  27.912 26.197 29.4 27.635 ;
  END
END qfd_rlyh0_128_EW_65x30
END LIBRARY
